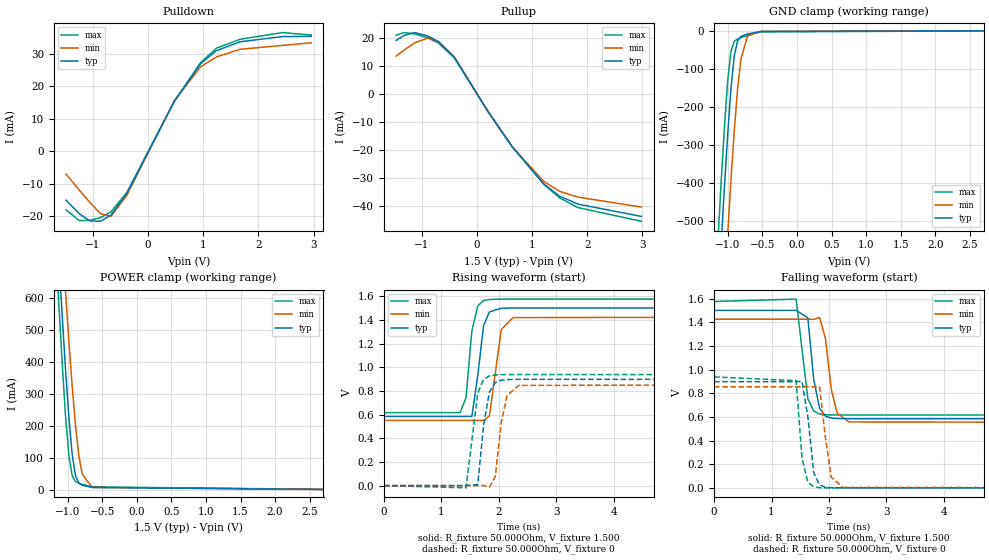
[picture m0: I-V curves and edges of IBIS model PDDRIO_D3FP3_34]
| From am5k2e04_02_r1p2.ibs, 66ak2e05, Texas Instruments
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|2.66MA OUTPUT CURRENT SETTING WITH 200 OHM INT. TERM.
|   Model PDDRIO_D3FP3_34
[Model] PDDRIO_D3FP3_34
Model_type   I/O
Polarity   Non-Inverting
Enable   Active-High
C_comp   3.236pF   3.174pF   3.318pF
C_comp_pullup   516.723fF   493.565fF   544.031fF
C_comp_pulldown 2.715pF   2.675pF   2.769pF
Vinh = 925.000mV
Vinl = 575.000mV
Vmeas = 750.000mV
Vref = 750.000mV
Rref = 50Ohms
Cref = 0pF
[Model Spec]
Vinh   925.000mV   888.000mV   963.000mV
Vinl   575.000mV   538.000mV   613.000mV
Vmeas   750.000mV   713.000mV   788.000mV
Vref   750.000mV   713.000mV   788.000mV
[Temperature Range]   25.000   125.000   -40.000
[Voltage Range]   1.500V   1.425V   1.575V
[GND Clamp Reference]   0.00V   0.00V   0.00V
|[C Comp Corner]
| variable   typ   min   max
|C_comp   3.236pF   3.318pF   3.174pF
|C_comp_pullup   516.723fF   544.031fF   493.565fF
|C_comp_pulldown   2.715pF   2.769pF   2.675pF
[Pulldown Reference]   0.00V   0.00V   0.00V
[POWER Clamp Reference]   1.500V   1.425V   1.575V
[Pullup Reference]   1.500V   1.425V   1.575V
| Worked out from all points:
|   slope of the pulldown table from 0 to 0.225 V, typ, clamps not added: 29.7 ohm
|   slope of the pullup table from 0 to 0.225 V, typ, clamps not added: 32 ohm
|   GND clamp passes 1 mA (typ) near -0.49 V on its own axis
|   POWER clamp passes 1 mA (typ) near -0.46 V on its own axis
|   rising waveform, R_fixture 50.000Ohm, V_fixture 1.500: 20-80 % time 141ps typ, 149ps min, 127ps max; typ from 0.584 V to 1.5 V
|   rising waveform, R_fixture 50.000Ohm, V_fixture 0: 20-80 % time 143ps typ, 149ps min, 143ps max; typ from 0 V to 0.898 V
|   falling waveform, R_fixture 50.000Ohm, V_fixture 1.500: 20-80 % time 141ps typ, 153ps min, 143ps max; typ from 1.5 V to 0.584 V
|   falling waveform, R_fixture 50.000Ohm, V_fixture 0: 20-80 % time 131ps typ, 139ps min, 110ps max; typ from 0.898 V to 0 V
[GND Clamp]
-1.48V    -1.918A    -2.181A    -1.764A
-1.145V   -723.4mA   -1.002A    -556.7mA
-1.098V   -563.3mA   -840.4mA   -399.2mA
-1.05V    -410.5mA   -683.3mA   -253.2mA
-1.002V   -269.5mA   -532mA     -130mA
-954.6mV  -149.1mA   -389.4mA   -52.57mA
-906.8mV  -64.77mA   -260.1mA   -27.53mA
-859.1mV  -26.06mA   -151.5mA   -21.41mA
-811.4mV  -14.61mA   -73.73mA   -17.98mA
-715.9mV  -8.245mA   -13.8mA    -12.04mA
-525mV    -1.646mA   -1.444mA   -2.745mA
2.959V    5.131nA    157.9nA    5.129nA
[Power Clamp]
-1.459V   2.052A     2.172A     2.008A
-1.173V   897.3mA    1.113A     766.5mA
-1.125V   714.9mA    943mA      572.9mA
-1.077V   539.1mA    776.9mA    390mA
-1.03V    373.7mA    616.2mA    227.4mA
-981.8mV  225.9mA    463.5mA    105.8mA
-934.1mV  109.7mA    322.9mA    43.29mA
-886.4mV  43.23mA    201.1mA    25.08mA
-838.6mV  20.27mA    107.7mA    20.03mA
-790.9mV  13.81mA    49.43mA    16.8mA
-647.7mV  6.613mA    6.926mA    8.545mA
2.98V     -9.151nA   -320.3nA   -14.09nA
[Pulldown]
-1.48V    -15mA      -7mA       -18mA
-1.241V   -19.2mA    -11.9mA    -21.3mA
-1.05V    -21.4mA    -15.7mA    -21.2mA
-859.1mV  -21.51mA   -19.1mA    -20.39mA
-668.2mV  -19.6mA    -20.06mA   -18.62mA
-381.8mV  -12.99mA   -13.57mA   -12.7mA
477.3mV   15.34mA    15.48mA    15.28mA
954.6mV   26.95mA    26.01mA    27.3mA
1.241V    30.97mA    29.06mA    31.74mA
1.67V     33.71mA    31.4mA     34.48mA
2.434V    35.3mA     32.6mA     36.55mA
2.959V    35.4mA     33.4mA     35.8mA
[Pullup]
-1.459V   19mA       13.36mA    20.87mA
-1.316V   20.8mA     15.54mA    21.8mA
-1.125V   21.8mA     18.14mA    21.31mA
-886.4mV  20.58mA    19.86mA    19.93mA
-695.5mV  18.6mA     18.6mA     18.08mA
-409.1mV  13.07mA    13.17mA    12.79mA
211.4mV   -6.617mA   -6.664mA   -6.54mA
640.9mV   -18.99mA   -18.93mA   -18.85mA
1.214V    -32.21mA   -31.33mA   -32.34mA
1.5V      -36.58mA   -34.84mA   -37.18mA
1.834V    -39.41mA   -36.92mA   -40.66mA
2.98V     -43.8mA    -40.46mA   -45.54mA
[Ramp]
R_load=50.000Ohm
dV/dt_r   544.140mV/124.000ps  518.489mV/133.000ps  569.040mV/116.000ps
dV/dt_f   544.140mV/112.500ps  518.489mV/122.500ps  569.040mV/107.000ps
[Rising waveform]
R_fixture=50.000Ohm
V_fixture=1.500
V_fixture_min=1.425
V_fixture_max=1.575
0s        583.8mV    550.7mV    615.9mV
1.327ns   583.8mV    550.7mV    616mV
1.429ns   583.8mV    550.7mV    742.7mV
1.531ns   583.7mV    550.7mV    1.307V
1.633ns   926.8mV    550.8mV    1.517V
1.735ns   1.352V     549.4mV    1.563V
1.837ns   1.467V     587.9mV    1.572V
2.042ns   1.498V     1.317V     1.575V
2.246ns   1.5V       1.419V     1.575V
10ns      1.5V       1.425V     1.575V
[Rising waveform]
R_fixture=50.000Ohm
V_fixture=0
0s        0V         1.817uV    0V
1.429ns   31.28uV    -4.413uV   -19.23mV
1.633ns   9.079mV    13.97uV    780mV
1.735ns   508.2mV    595.4uV    897.6mV
1.837ns   791.1mV    -12.61mV   926.8mV
1.939ns   869.8mV    76.84mV    934.7mV
2.042ns   889.7mV    530.4mV    936.9mV
2.144ns   895.2mV    761.1mV    937.5mV
2.348ns   897.4mV    846.2mV    937.7mV
10ns      897.6mV    854mV      937.7mV
[Falling waveform]
R_fixture=50.000Ohm
V_fixture=1.500
V_fixture_min=1.425
V_fixture_max=1.575
0s        1.5V       1.425V     1.575V
1.429ns   1.5V       1.425V     1.595V
1.633ns   1.436V     1.425V     752.2mV
1.735ns   917.1mV    1.424V     649.2mV
1.837ns   671.9mV    1.44V      624.7mV
1.939ns   606.3mV    1.265V     618.2mV
2.042ns   590mV      830.6mV    616.5mV
2.144ns   585.6mV    631.8mV    616.1mV
2.348ns   583.9mV    557.3mV    615.9mV
10ns      583.8mV    550.7mV    615.9mV
[Falling waveform]
R_fixture=50.000Ohm
V_fixture=0
0s        897.6mV    854mV      937.7mV
1.429ns   897.6mV    854mV      906.4mV
1.531ns   899.6mV    854mV      251.3mV
1.633ns   601.6mV    854mV      48mV
1.735ns   128.5mV    853.8mV    9.098mV
1.837ns   25.25mV    854.6mV    1.631mV
1.939ns   4.886mV    424.7mV    370.7uV
2.042ns   874.4uV    88.61mV    -26.56uV
2.246ns   25.9uV     3.703mV    0V
10ns      0V         1.816uV    0V
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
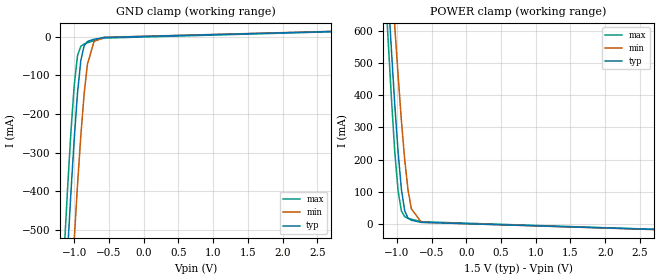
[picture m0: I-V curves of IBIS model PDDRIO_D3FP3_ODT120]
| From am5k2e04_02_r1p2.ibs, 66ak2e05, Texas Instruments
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|   Model PDDRIO_D3FP3_ODT120
[Model] PDDRIO_D3FP3_ODT120
Model_type   Input
Polarity   Non-Inverting
Enable   Active-High
C_comp   3.260pF   3.200pF   3.350pF
C_comp_pullup   547.386fF   525.260fF   584.423fF
C_comp_pulldown 2.708pF   2.670pF   2.760pF
Vinh = 925.000mV
Vinl = 575.000mV
[Temperature Range]   25.000   125.000   -40.000
[Voltage Range]   1.500V   1.425V   1.575V
[GND Clamp Reference]   0.00V   0.00V   0.00V
|[C Comp Corner]
| variable   typ   min   max
|C_comp 3.260pF   3.350pF   3.200pF
|C_comp_pullup 547.386fF   584.423fF   525.260fF
|C_comp_pulldown 2.708pF   2.760pF   2.670pF
[POWER Clamp Reference]   1.500V   1.425V   1.575V
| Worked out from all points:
|   GND clamp passes 1 mA (typ) near -0.53 V on its own axis
|   POWER clamp passes 1 mA (typ) near -0.47 V on its own axis
[GND Clamp]
-1.48V    -1.91A     -2.171A    -1.756A
-1.145V   -718.6mA   -995.7mA   -552.2mA
-1.098V   -559mA     -835mA     -395.1mA
-1.05V    -406.6mA   -678.3mA   -249.4mA
-1.002V   -266mA     -527.6mA   -126.5mA
-954.6mV  -146mA     -385.5mA   -49.45mA
-906.8mV  -62.03mA   -256.7mA   -24.72mA
-859.1mV  -23.65mA   -148.6mA   -18.89mA
-811.4mV  -12.49mA   -71.22mA   -15.74mA
-715.9mV  -6.656mA   -12.08mA   -10.34mA
-572.7mV  -1.961mA   -1.652mA   -3.583mA
2.959V    14.61mA    15.11mA    14.06mA
[Power Clamp]
-1.459V   2.046A     2.165A     2.003A
-1.173V   893.9mA    1.109A     763.1mA
-1.125V   711.7mA    939.1mA    569.8mA
-1.077V   536.2mA    773.5mA    387.1mA
-1.03V    371.1mA    613.2mA    224.9mA
-981.8mV  223.5mA    460.9mA    103.5mA
-934.1mV  107.7mA    320.6mA    41.3mA
-886.4mV  41.46mA    199.1mA    23.34mA
-838.6mV  18.76mA    106mA      18.52mA
-790.9mV  12.5mA     48.03mA    15.49mA
-647.7mV  5.868mA    6.184mA    7.808mA
2.98V     -17.73mA   -18.38mA   -17.59mA
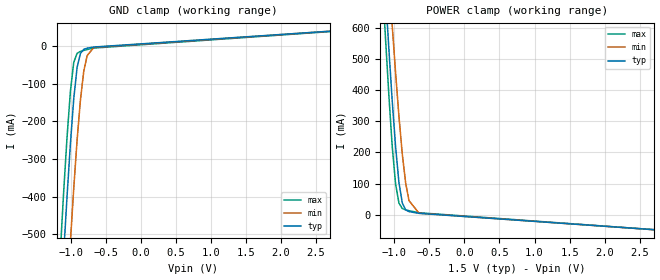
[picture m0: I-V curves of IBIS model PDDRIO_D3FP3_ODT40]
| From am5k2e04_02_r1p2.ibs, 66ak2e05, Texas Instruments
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|   Model PDDRIO_D3FP3_ODT40
[Model] PDDRIO_D3FP3_ODT40
Model_type   Input
Polarity   Non-Inverting
Enable   Active-High
C_comp   3.309pF   3.232pF   3.410pF
C_comp_pullup   607.833fF   563.222fF   663.200fF
C_comp_pulldown 2.696pF   2.664pF   2.742pF
Vinh = 925.000mV
Vinl = 575.000mV
[Temperature Range]   25.000   125.000   -40.000
[Voltage Range]   1.500V   1.425V   1.575V
[GND Clamp Reference]   0.00V   0.00V   0.00V
|[C Comp Corner]
| variable   typ   min   max
|C_comp 3.309pF   3.410pF   3.232pF
|C_comp_pullup 607.833fF   663.200fF   563.222fF
|C_comp_pulldown 2.696pF   2.742pF   2.664pF
[POWER Clamp Reference]   1.500V   1.425V   1.575V
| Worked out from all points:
|   GND clamp passes 1 mA (typ) near -0.62 V on its own axis
|   POWER clamp passes 1 mA (typ) near -0.51 V on its own axis
[GND Clamp]
-1.48V    -1.895A    -2.153A    -1.741A
-1.145V   -709.5mA   -984.5mA   -543.3mA
-1.098V   -550.7mA   -824.6mA   -386.7mA
-1.05V    -399.2mA   -669mA     -241.7mA
-1.002V   -259.3mA   -519.2mA   -119.6mA
-954.6mV  -140.1mA   -378mA     -43.12mA
-906.8mV  -56.72mA   -250.1mA   -19.02mA
-859.1mV  -18.96mA   -142.9mA   -13.8mA
-811.4mV  -8.364mA   -66.45mA   -11.23mA
-763.6mV  -5.242mA   -25.24mA   -9.016mA
-668.2mV  -2.238mA   -3.25mA    -4.954mA
2.959V    43.1mA     43.05mA    42.16mA
[Power Clamp]
-1.459V   2.035A     2.153A     1.992A
-1.173V   887.1mA    1.101A     756.5mA
-1.125V   705.6mA    932mA      563.6mA
-1.077V   530.6mA    767.1mA    381.5mA
-1.03V    366mA      607.5mA    219.8mA
-981.8mV  219mA      455.8mA    99.02mA
-934.1mV  103.7mA    316.2mA    37.4mA
-886.4mV  38.01mA    195.4mA    19.95mA
-838.6mV  15.8mA     102.8mA    15.55mA
-790.9mV  9.964mA    45.44mA    12.94mA
-647.7mV  4.428mA    4.813mA    6.354mA
2.98V     -52.32mA   -52.48mA   -52.49mA
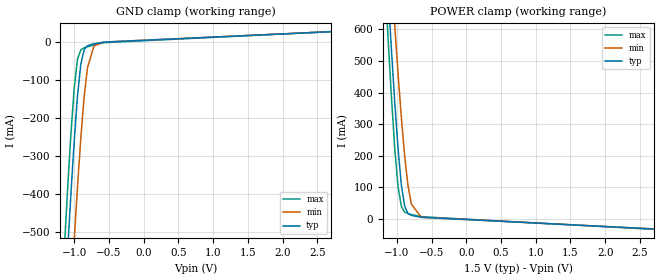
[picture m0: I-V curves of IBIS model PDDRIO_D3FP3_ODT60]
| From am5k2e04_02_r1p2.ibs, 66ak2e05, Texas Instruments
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|   Model PDDRIO_D3FP3_ODT60
[Model] PDDRIO_D3FP3_ODT60
Model_type   Input
Polarity   Non-Inverting
Enable   Active-High
C_comp   3.286pF   3.226pF   3.386pF
C_comp_pullup   579.570fF   555.779fF   632.377fF
C_comp_pulldown 2.701pF   2.664pF   2.749pF
Vinh = 925.000mV
Vinl = 575.000mV
[Temperature Range]   25.000   125.000   -40.000
[Voltage Range]   1.500V   1.425V   1.575V
[GND Clamp Reference]   0.00V   0.00V   0.00V
|[C Comp Corner]
|| variable   typ   min   max
|C_comp 3.286pF   3.386pF   3.226pF
|C_comp_pullup 579.570fF   632.377fF   555.779fF
|C_comp_pulldown 2.701pF   2.749pF   2.664pF
[POWER Clamp Reference]   1.500V   1.425V   1.575V
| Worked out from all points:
|   GND clamp passes 1 mA (typ) near -0.57 V on its own axis
|   POWER clamp passes 1 mA (typ) near -0.49 V on its own axis
[GND Clamp]
-1.48V    -1.903A    -2.162A    -1.748A
-1.145V   -714.3mA   -990.3mA   -547.5mA
-1.098V   -555mA     -830mA     -390.6mA
-1.05V    -403mA     -673.8mA   -245.3mA
-1.002V   -262.8mA   -523.6mA   -122.8mA
-954.6mV  -143.1mA   -382mA     -46.1mA
-906.8mV  -59.45mA   -253.5mA   -21.71mA
-859.1mV  -21.36mA   -145.9mA   -16.2mA
-811.4mV  -10.48mA   -68.97mA   -13.36mA
-715.9mV  -5.153mA   -10.58mA   -8.539mA
-572.7mV  -1.072mA   -892.8uA   -2.551mA
2.959V    28.5mA     28.54mA    29.03mA
[Power Clamp]
-1.459V   2.041A     2.159A     1.997A
-1.173V   890.5mA    1.105A     759.5mA
-1.125V   708.7mA    935.7mA    566.5mA
-1.077V   533.5mA    770.4mA    384.2mA
-1.03V    368.6mA    610.4mA    222.1mA
-981.8mV  221.3mA    458.4mA    101.1mA
-934.1mV  105.7mA    318.4mA    39.23mA
-886.4mV  39.75mA    197.3mA    21.55mA
-838.6mV  17.3mA     104.4mA    16.95mA
-790.9mV  11.26mA    46.79mA    14.14mA
-647.7mV  5.169mA    5.52mA     7.041mA
2.98V     -34.6mA    -34.72mA   -36.16mA
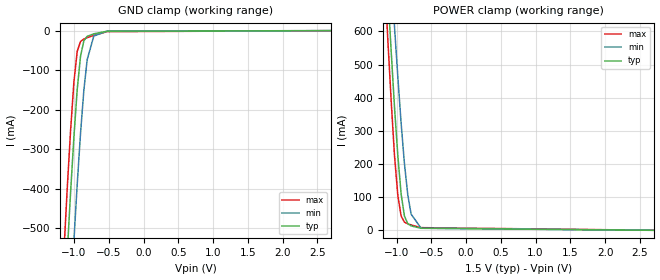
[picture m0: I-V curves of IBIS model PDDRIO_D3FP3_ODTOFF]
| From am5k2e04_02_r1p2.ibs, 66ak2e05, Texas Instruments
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|   Model PDDRIO_D3FP3_ODTOFF
[Model] PDDRIO_D3FP3_ODTOFF
Model_type   Input
Polarity   Non-Inverting
Enable   Active-High
C_comp   3.236pF   3.174pF   3.318pF
C_comp_pullup   530.516fF   508.082fF   557.434fF
C_comp_pulldown 2.701pF   2.661pF   2.755pF
Vinh = 925.000mV
Vinl = 575.000mV
[Temperature Range]   25.000   125.000   -40.000
[Voltage Range]   1.500V   1.425V   1.575V
[GND Clamp Reference]   0.00V   0.00V   0.00V
|[C Comp Corner]
|| variable   typ   min   max
|C_comp 3.236pF   3.318pF   3.174pF
|C_comp_pullup 530.516fF   557.434fF   508.082fF
|C_comp_pulldown 2.701pF   2.755pF   2.661pF
[POWER Clamp Reference]   1.500V   1.425V   1.575V
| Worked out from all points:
|   GND clamp passes 1 mA (typ) near -0.49 V on its own axis
|   POWER clamp passes 1 mA (typ) near -0.46 V on its own axis
[GND Clamp]
-1.48V    -1.918A    -2.181A    -1.764A
-1.145V   -723.4mA   -1.002A    -556.7mA
-1.098V   -563.3mA   -840.4mA   -399.2mA
-1.05V    -410.5mA   -683.3mA   -253.2mA
-1.002V   -269.5mA   -532mA     -130mA
-954.6mV  -149.1mA   -389.4mA   -52.57mA
-906.8mV  -64.77mA   -260.1mA   -27.53mA
-859.1mV  -26.06mA   -151.5mA   -21.41mA
-811.4mV  -14.61mA   -73.73mA   -17.98mA
-715.9mV  -8.245mA   -13.8mA    -12.04mA
-525mV    -1.646mA   -1.444mA   -2.745mA
2.959V    5.131nA    157.9nA    7.042nA
[Power Clamp]
-1.459V   2.052A     2.172A     2.008A
-1.173V   897.3mA    1.113A     766.5mA
-1.125V   714.9mA    943mA      572.9mA
-1.077V   539.1mA    776.9mA    390mA
-1.03V    373.7mA    616.2mA    227.4mA
-981.8mV  225.9mA    463.5mA    105.8mA
-934.1mV  109.7mA    322.9mA    43.29mA
-886.4mV  43.23mA    201.1mA    25.08mA
-838.6mV  20.27mA    107.7mA    20.03mA
-790.9mV  13.81mA    49.43mA    16.8mA
-647.7mV  6.613mA    6.926mA    8.545mA
2.98V     -9.151nA   -320.3nA   -14.09nA
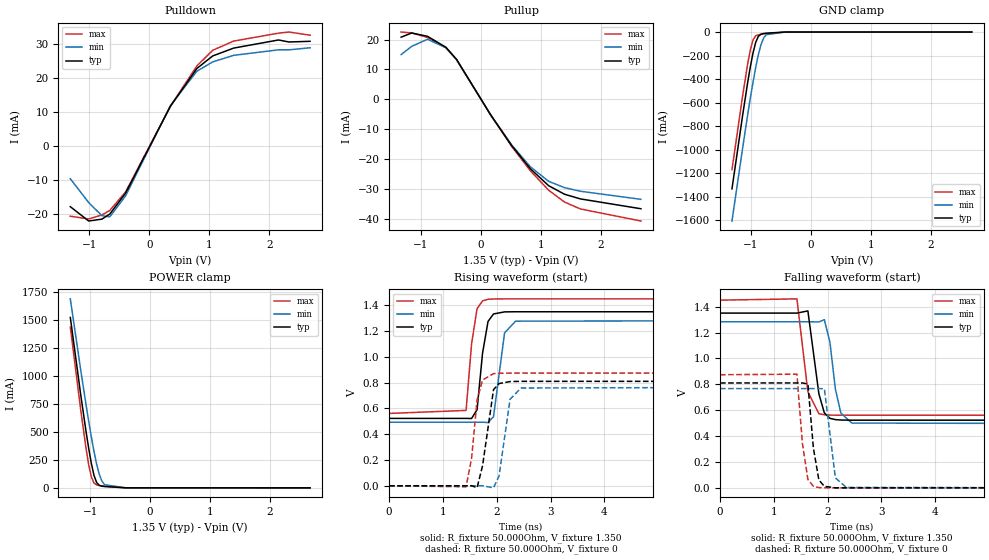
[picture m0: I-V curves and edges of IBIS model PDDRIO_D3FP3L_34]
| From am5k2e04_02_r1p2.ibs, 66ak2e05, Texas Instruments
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|   Model PDDRIO_D3FP3L_34
[Model] PDDRIO_D3FP3L_34
Model_type   I/O
Polarity   Non-Inverting
Enable   Active-High
C_comp   3.244pF   3.179pF   3.327pF
C_comp_pullup   525.014fF   499.307fF   553.259fF
C_comp_pulldown 2.714pF   2.675pF   2.768pF
Vinh = 810.000mV
Vinl = 540.000mV
Vmeas = 675.000mV
Vref = 675.000mV
Rref = 50Ohms
Cref = 0pF
[Model Spec]
Vinh   810.000mV   777.000mV   860.000mV
Vinl   540.000mV   507.000mV   590.000mV
Vmeas   675.000mV   642.000mV   725.000mV
Vref   675.000mV   642.000mV   725.000mV
[Temperature Range]   25.000   125.000   -40.000
[Voltage Range]   1.350V   1.283V   1.450V
[GND Clamp Reference]   0.00V   0.00V   0.00V
|[C Comp Corner]
| variable   typ   min   max
|C_comp 3.244pF   3.327pF   3.179pF
|C_comp_pullup 525.014fF   553.259fF   499.307fF
|C_comp_pulldown 2.714pF   2.768pF   2.675pF
[Pulldown Reference]   0.00V   0.00V   0.00V
[POWER Clamp Reference]   1.350V   1.283V   1.450V
[Pullup Reference]   1.350V   1.283V   1.450V
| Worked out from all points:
|   slope of the pulldown table from 0 to 0.203 V, typ, clamps not added: 29.1 ohm
|   slope of the pullup table from 0 to 0.203 V, typ, clamps not added: 31.5 ohm
|   GND clamp passes 1 mA (typ) near -0.49 V on its own axis
|   POWER clamp passes 1 mA (typ) near -0.46 V on its own axis
|   rising waveform, R_fixture 50.000Ohm, V_fixture 1.350: 20-80 % time 144ps typ, 151ps min, 136ps max; typ from 0.523 V to 1.35 V
|   rising waveform, R_fixture 50.000Ohm, V_fixture 0: 20-80 % time 144ps typ, 156ps min, 141ps max; typ from 0 V to 0.81 V
|   falling waveform, R_fixture 50.000Ohm, V_fixture 1.350: 20-80 % time 157ps typ, 163ps min, 142ps max; typ from 1.35 V to 0.523 V
|   falling waveform, R_fixture 50.000Ohm, V_fixture 0: 20-80 % time 130ps typ, 139ps min, 130ps max; typ from 0.81 V to 0 V
[GND Clamp]
-1.318V   -1.332A    -1.605A    -1.169A
-1.142V   -713.1mA   -991.3mA   -546.4mA
-1.055V   -424.6mA   -698mA     -266.3mA
-1.011V   -292.9mA   -557.9mA   -149mA
-966.7mV  -177mA     -424.6mA   -66.54mA
-922.7mV  -87.81mA   -301.3mA   -32.09mA
-878.8mV  -37.14mA   -193.2mA   -23.25mA
-834.9mV  -18.49mA   -107.6mA   -19.58mA
-790.9mV  -12.57mA   -51.47mA   -16.65mA
-747mV    -9.756mA   -23.13mA   -13.9mA
-439.4mV  -371uA     -394.7uA   -656.8uA
2.68V     4.17nA     252.6nA    2.491nA
[Power Clamp]
-1.33V    1.525A     1.691A     1.439A
-1.155V   827.2mA    1.048A     691.5mA
-1.067V   501.3mA    740.6mA    350.5mA
-1.023V   351.3mA    593.8mA    204.8mA
-978.8mV  217.4mA    454mA      97mA
-934.9mV  111.2mA    324.7mA    43.08mA
-890.9mV  47.28mA    211.3mA    25.9mA
-847mV    22.44mA    121mA      20.68mA
-803mV    14.88mA    60.26mA    17.58mA
-759.1mV  11.71mA    27.92mA    14.82mA
-407.6mV  326.5uA    576uA      395.5uA
2.668V    -7.545nA   -288.5nA   -3.819nA
[Pulldown]
-1.318V   -17.8mA    -9.6mA     -20.6mA
-1.011V   -22mA      -16.6mA    -21.4mA
-790.9mV  -21.45mA   -20.44mA   -20.23mA
-659.1mV  -19.95mA   -20.77mA   -18.89mA
-395.5mV  -13.8mA    -14.61mA   -13.44mA
351.5mV   11.67mA    11.86mA    11.67mA
790.9mV   22.71mA    21.91mA    23.45mA
1.055V    26.4mA     24.66mA    28.06mA
1.406V    28.71mA    26.59mA    30.77mA
2.153V    31.09mA    28.2mA     33.09mA
2.329V    30.5mA     28.2mA     33.42mA
2.68V     30.7mA     28.8mA     32.5mA
[Pullup]
-1.33V    20.8mA     14.97mA    22.52mA
-1.155V   22.2mA     17.72mA    22.23mA
-890.9mV  21.09mA    20.1mA     20.71mA
-583.3mV  17.42mA    17.28mA    17.21mA
-407.6mV  13.39mA    13.38mA    13.29mA
163.6mV   -5.229mA   -5.207mA   -5.266mA
515.1mV   -15.54mA   -15.31mA   -15.79mA
822.7mV   -23.18mA   -22.52mA   -23.85mA
1.13V     -28.9mA    -27.44mA   -30.41mA
1.394V    -31.74mA   -29.54mA   -34.35mA
1.658V    -33.3mA    -30.74mA   -36.66mA
2.668V    -36.6mA    -33.45mA   -40.7mA
[Ramp]
R_load=50.000Ohm
dV/dt_r   491.250mV/127.500ps  467.070mV/138.000ps  528.840mV/117.000ps
dV/dt_f   491.250mV/117.500ps  467.070mV/128.500ps  528.840mV/109.000ps
[Rising waveform]
R_fixture=50.000Ohm
V_fixture=1.350
V_fixture_min=1.283
V_fixture_max=1.450
0s        522.7mV    493.1mV    561.2mV
1.429ns   522.7mV    493.1mV    584.7mV
1.531ns   522mV      493.2mV    1.1V
1.633ns   589.6mV    493.2mV    1.374V
1.735ns   1.029V     493.2mV    1.434V
1.837ns   1.275V     490.4mV    1.447V
1.939ns   1.333V     535.8mV    1.449V
2.144ns   1.349V     1.186V     1.45V
2.348ns   1.35V      1.277V     1.45V
10ns      1.35V      1.283V     1.45V
[Rising waveform]
R_fixture=50.000Ohm
V_fixture=0
0s        0V         1.612uV    0V
1.429ns   -3.209uV   -2.435uV   -7.957mV
1.531ns   268.9uV    4.198uV    210.7mV
1.633ns   -15.18mV   -5.69uV    666mV
1.735ns   154.9mV    12.74uV    820.5mV
1.939ns   746mV      -16.11mV   870mV
2.042ns   792.8mV    77.12mV    873mV
2.246ns   808.6mV    670.8mV    874mV
2.45ns    810.1mV    758.4mV    874mV
10ns      810.2mV    767mV      874mV
[Falling waveform]
R_fixture=50.000Ohm
V_fixture=1.350
V_fixture_min=1.283
V_fixture_max=1.450
0s        1.35V      1.283V     1.45V
1.429ns   1.35V      1.283V     1.46V
1.633ns   1.367V     1.283V     741.7mV
1.837ns   726.7mV    1.282V     572.7mV
1.939ns   578.8mV    1.299V     564.3mV
2.042ns   537.2mV    1.126V     562mV
2.144ns   527.1mV    762.3mV    561.4mV
2.246ns   524mV      577.3mV    561.3mV
2.45ns    522.8mV    500.6mV    561.2mV
10ns      522.7mV    493.1mV    561.2mV
[Falling waveform]
R_fixture=50.000Ohm
V_fixture=0
0s        810.2mV    767mV      874mV
1.429ns   810.3mV    767mV      878mV
1.531ns   810.1mV    767mV      343.6mV
1.633ns   802.8mV    767mV      65.29mV
1.735ns   307.7mV    766.9mV    12.1mV
1.837ns   60.73mV    767.2mV    2.23mV
1.939ns   11.86mV    765mV      389.5uV
2.144ns   405.8uV    76.53mV    9.251uV
2.348ns   9.743uV    3.208mV    0V
10ns      0V         1.616uV    0V
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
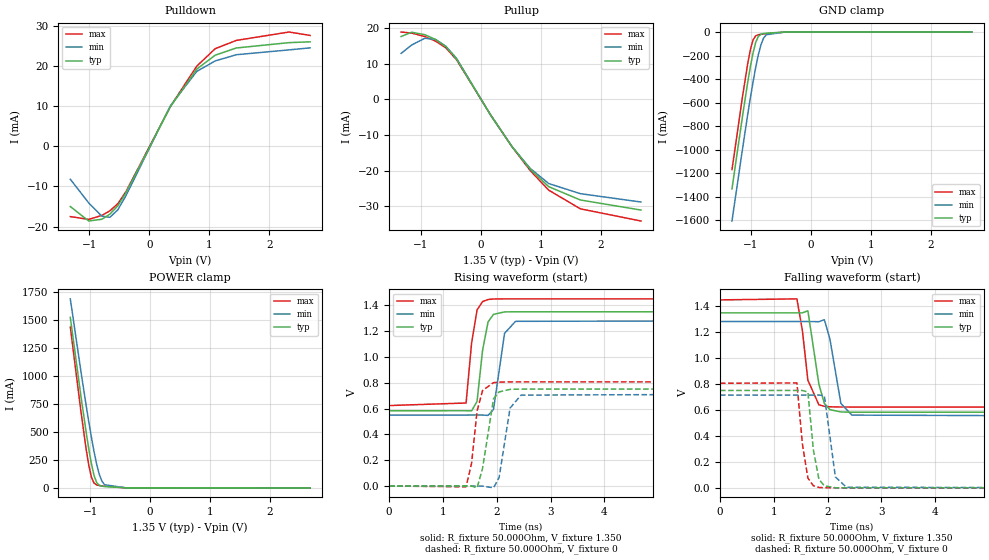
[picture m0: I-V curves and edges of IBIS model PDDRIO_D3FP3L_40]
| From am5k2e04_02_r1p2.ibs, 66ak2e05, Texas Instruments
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|   Model PDDRIO_D3FP3L_40
[Model] PDDRIO_D3FP3L_40
Model_type   I/O
Polarity   Non-Inverting
Enable   Active-High
C_comp   3.244pF   3.179pF   3.327pF
C_comp_pullup   525.014fF   499.307fF   553.259fF
C_comp_pulldown 2.714pF   2.675pF   2.768pF
Vinh = 810.000mV
Vinl = 540.000mV
Vmeas = 675.000mV
Vref = 675.000mV
Rref = 50Ohms
Cref = 0pF
[Model Spec]
Vinh   810.000mV   777.000mV   860.000mV
Vinl   540.000mV   507.000mV   590.000mV
Vmeas   675.000mV   642.000mV   725.000mV
Vref   675.000mV   642.000mV   725.000mV
[Temperature Range]   25.000   125.000   -40.000
[Voltage Range]   1.350V   1.283V   1.450V
[GND Clamp Reference]   0.00V   0.00V   0.00V
|[C Comp Corner]
| variable   typ   min   max
|C_comp 3.244pF   3.327pF   3.179pF
|C_comp_pullup 525.014fF   553.259fF   499.307fF
|C_comp_pulldown 2.714pF   2.768pF   2.675pF
[Pulldown Reference]   0.00V   0.00V   0.00V
[POWER Clamp Reference]   1.350V   1.283V   1.450V
[Pullup Reference]   1.350V   1.283V   1.450V
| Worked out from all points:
|   slope of the pulldown table from 0 to 0.203 V, typ, clamps not added: 34.4 ohm
|   slope of the pullup table from 0 to 0.203 V, typ, clamps not added: 37.2 ohm
|   GND clamp passes 1 mA (typ) near -0.49 V on its own axis
|   POWER clamp passes 1 mA (typ) near -0.46 V on its own axis
|   rising waveform, R_fixture 50.000Ohm, V_fixture 1.350: 20-80 % time 149ps typ, 155ps min, 141ps max; typ from 0.583 V to 1.35 V
|   rising waveform, R_fixture 50.000Ohm, V_fixture 0: 20-80 % time 155ps typ, 165ps min, 152ps max; typ from 0 V to 0.751 V
|   falling waveform, R_fixture 50.000Ohm, V_fixture 1.350: 20-80 % time 170ps typ, 174ps min, 161ps max; typ from 1.35 V to 0.583 V
|   falling waveform, R_fixture 50.000Ohm, V_fixture 0: 20-80 % time 135ps typ, 143ps min, 135ps max; typ from 0.751 V to 0 V
[GND Clamp]
-1.318V   -1.332A    -1.605A    -1.169A
-1.142V   -713.1mA   -991.3mA   -546.4mA
-1.055V   -424.6mA   -698mA     -266.3mA
-1.011V   -292.9mA   -557.9mA   -149mA
-966.7mV  -177mA     -424.6mA   -66.54mA
-922.7mV  -87.81mA   -301.3mA   -32.09mA
-878.8mV  -37.14mA   -193.2mA   -23.25mA
-834.9mV  -18.49mA   -107.6mA   -19.58mA
-790.9mV  -12.57mA   -51.47mA   -16.65mA
-747mV    -9.756mA   -23.13mA   -13.9mA
-439.4mV  -371uA     -394.7uA   -656.8uA
2.68V     4.17nA     252.6nA    785.5pA
[Power Clamp]
-1.33V    1.525A     1.691A     1.439A
-1.155V   827.2mA    1.048A     691.5mA
-1.067V   501.3mA    740.6mA    350.5mA
-1.023V   351.3mA    593.8mA    204.8mA
-978.8mV  217.4mA    454mA      97mA
-934.9mV  111.2mA    324.7mA    43.08mA
-890.9mV  47.28mA    211.3mA    25.9mA
-847mV    22.44mA    121mA      20.68mA
-803mV    14.88mA    60.26mA    17.58mA
-759.1mV  11.71mA    27.92mA    14.82mA
-407.6mV  326.4uA    576uA      395.5uA
2.668V    -7.545nA   -288.5nA   181.4pA
[Pulldown]
-1.318V   -15mA      -8.2mA     -17.5mA
-1.011V   -18.6mA    -14.1mA    -18.2mA
-790.9mV  -18.16mA   -17.4mA    -17.2mA
-659.1mV  -16.89mA   -17.68mA   -16.07mA
-527.3mV  -14.84mA   -15.84mA   -14.31mA
-395.5mV  -11.68mA   -12.44mA   -11.43mA
351.5mV   9.877mA    10.1mA     9.93mA
790.9mV   19.22mA    18.65mA    19.95mA
1.098V    22.68mA    21.25mA    24.3mA
1.45V     24.47mA    22.79mA    26.36mA
2.329V    25.8mA     24mA       28.44mA
2.68V     26mA       24.5mA     27.6mA
[Pullup]
-1.33V    17.6mA     12.87mA    18.85mA
-1.155V   18.8mA     15.21mA    18.55mA
-934.9mV  18.1mA     17.11mA    17.59mA
-759.1mV  16.79mA    16.79mA    16.33mA
-583.3mV  14.74mA    14.85mA    14.4mA
-407.6mV  11.33mA    11.5mA     11.12mA
163.6mV   -4.424mA   -4.475mA   -4.405mA
515.1mV   -13.15mA   -13.16mA   -13.21mA
822.7mV   -19.61mA   -19.35mA   -19.95mA
1.13V     -24.45mA   -23.58mA   -25.43mA
1.658V    -28.18mA   -26.41mA   -30.65mA
2.668V    -31mA      -28.75mA   -34.07mA
[Ramp]
R_load=50.000Ohm
dV/dt_r   455.430mV/137.500ps  434.609mV/148.500ps  490.050mV/127.000ps
dV/dt_f   455.430mV/128.000ps  434.609mV/139.500ps  490.050mV/119.500ps
[Rising waveform]
R_fixture=50.000Ohm
V_fixture=1.350
V_fixture_min=1.283
V_fixture_max=1.450
0s        583.3mV    550.1mV    623.5mV
1.429ns   583.4mV    550.1mV    643.2mV
1.531ns   582.5mV    550.2mV    1.106V
1.633ns   655.7mV    550.2mV    1.364V
1.735ns   1.05V      550.2mV    1.429V
1.837ns   1.271V     547.1mV    1.445V
1.939ns   1.33V      593.7mV    1.449V
2.144ns   1.349V     1.183V     1.45V
2.348ns   1.35V      1.276V     1.45V
10ns      1.35V      1.283V     1.45V
[Rising waveform]
R_fixture=50.000Ohm
V_fixture=0
0s        0V         1.784uV    0V
1.429ns   -2.136uV   -2.275uV   -6.185mV
1.531ns   261uV      4.249uV    176.1mV
1.633ns   -14.09mV   -4.032uV   579.8mV
1.735ns   136.6mV    8.763uV    740.4mV
1.939ns   675.6mV    -14.02mV   800.9mV
2.042ns   729.1mV    65.43mV    804.9mV
2.246ns   748.9mV    603.8mV    806.8mV
2.45ns    751mV      704.3mV    807mV
10ns      751.4mV    715.8mV    807mV
[Falling waveform]
R_fixture=50.000Ohm
V_fixture=1.350
V_fixture_min=1.283
V_fixture_max=1.450
0s        1.35V      1.283V     1.45V
1.429ns   1.35V      1.283V     1.458V
1.531ns   1.35V      1.283V     1.213V
1.633ns   1.366V     1.283V     830.3mV
1.837ns   800.1mV    1.282V     640.6mV
1.939ns   651.4mV    1.297V     628.9mV
2.042ns   603.3mV    1.148V     625.3mV
2.246ns   585.6mV    651.3mV    623.6mV
2.45ns    583.6mV    561.2mV    623.5mV
10ns      583.3mV    550.1mV    623.5mV
[Falling waveform]
R_fixture=50.000Ohm
V_fixture=0
0s        751.4mV    715.8mV    807mV
1.429ns   751.4mV    715.8mV    809.2mV
1.531ns   751.3mV    715.8mV    337.9mV
1.633ns   739.4mV    715.8mV    74.92mV
1.735ns   292.7mV    715.8mV    16.01mV
1.837ns   67.17mV    716.2mV    3.35mV
1.939ns   15.09mV    711.3mV    699.7uV
2.144ns   699.2uV    84.24mV    21.8uV
2.348ns   29.05uV    4.509mV    581.7nV
10ns      0V         1.783uV    0V
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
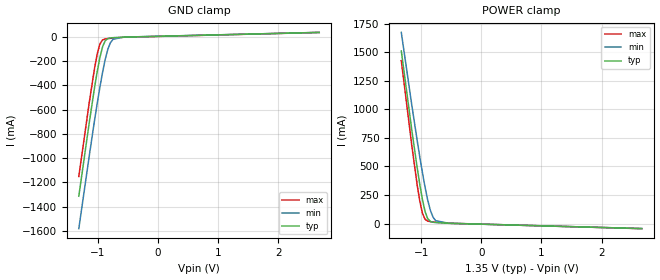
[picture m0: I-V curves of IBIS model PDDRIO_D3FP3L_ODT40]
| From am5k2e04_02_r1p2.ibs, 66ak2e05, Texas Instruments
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|   Model PDDRIO_D3FP3L_ODT40
[Model] PDDRIO_D3FP3L_ODT40
Model_type   Input
Polarity   Non-Inverting
Enable   Active-High
C_comp   3.382pF   3.290pF   3.488pF
C_comp_pullup   679.180fF   622.130fF   739.620fF
C_comp_pulldown 2.698pF   2.662pF   2.743pF
Vinh = 810.000mV
Vinl = 540.000mV
[Temperature Range]   25.000   125.000   -40.000
[Voltage Range]   1.350V   1.283V   1.450V
[GND Clamp Reference]   0.00V   0.00V   0.00V
|[C Comp Corner]
| variable   typ   min   max
|C_comp 3.382pF   3.488pF   3.290pF
|C_comp_pullup 679.180fF   739.620fF   622.130fF
|C_comp_pulldown 2.698pF   2.743pF   2.662pF
[POWER Clamp Reference]   1.350V   1.283V   1.450V
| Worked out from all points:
|   GND clamp passes 1 mA (typ) near -0.59 V on its own axis
|   POWER clamp passes 1 mA (typ) near -0.49 V on its own axis
[GND Clamp]
-1.318V   -1.315A    -1.583A    -1.152A
-1.142V   -700.3mA   -975mA     -533.5mA
-1.055V   -414.1mA   -684.4mA   -255.3mA
-1.011V   -283.4mA   -545.6mA   -138.8mA
-966.7mV  -168.5mA   -413.6mA   -57.25mA
-922.7mV  -80.27mA   -291.7mA   -23.67mA
-878.8mV  -30.43mA   -184.9mA   -15.65mA
-834.9mV  -12.56mA   -100.5mA   -12.76mA
-790.9mV  -7.364mA   -45.58mA   -10.6mA
-747mV    -5.246mA   -18.33mA   -8.59mA
-571.2mV  -624.2uA   -682.8uA   -1.81mA
2.68V     38.38mA    38.18mA    37.84mA
[Power Clamp]
-1.33V    1.512A     1.675A     1.427A
-1.155V   817.7mA    1.036A     681.9mA
-1.067V   493.2mA    731.3mA    342.3mA
-1.023V   344mA      585.5mA    197.3mA
-978.8mV  210.8mA    446.8mA    90.37mA
-934.9mV  105.5mA    318.4mA    37.31mA
-890.9mV  42.28mA    205.8mA    20.82mA
-847mV    18.12mA    116.3mA    16.21mA
-803mV    11.16mA    56.45mA    13.68mA
-759.1mV  8.54mA     24.8mA     11.48mA
-539.4mV  1.878mA    2.102mA    2.568mA
2.668V    -44.29mA   -44.5mA    -45.1mA
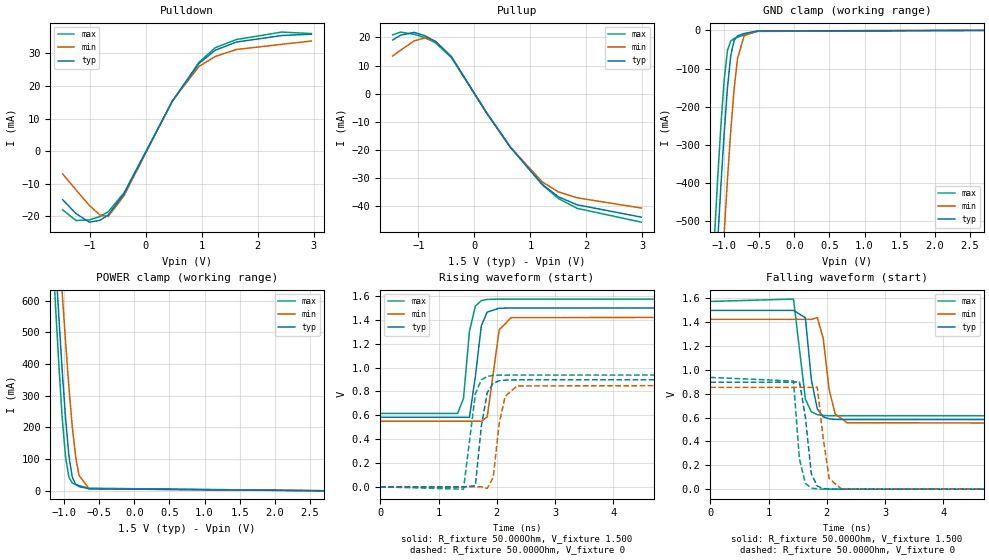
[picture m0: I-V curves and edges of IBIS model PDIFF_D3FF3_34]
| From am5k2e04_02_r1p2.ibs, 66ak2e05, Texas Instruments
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|   Model PDIFF_D3FF3_34
[Model] PDIFF_D3FF3_34
Model_type   I/O
Polarity   Non-Inverting
Enable   Active-High
C_comp   3.251pF   3.188pF   3.332pF
C_comp_pullup   516.830fF   493.667fF   544.031fF
C_comp_pulldown 2.728pF   2.688pF   2.782pF
Vinh = 925.000mV
Vinl = 575.000mV
Vmeas = 750.000mV
Vref = 750.000mV
Rref = 50Ohms
Cref = 0pF
[Model Spec]
Vinh   925.000mV   888.000mV   963.000mV
Vinl   575.000mV   538.000mV   613.000mV
Vmeas   750.000mV   713.000mV   788.000mV
Vref   750.000mV   713.000mV   788.000mV
[Temperature Range]   25.000   125.000   -40.000
[Voltage Range]   1.500V   1.425V   1.575V
[GND Clamp Reference]   0.00V   0.00V   0.00V
|[C Comp Corner]
| variable   typ   min   max
|C_comp 3.251pF   3.332pF   3.188pF
|C_comp_pullup 516.830fF   544.031fF   493.667fF
|C_comp_pulldown 2.728pF   2.782pF   2.688pF
[Pulldown Reference]   0.00V   0.00V   0.00V
[POWER Clamp Reference]   1.500V   1.425V   1.575V
[Pullup Reference]   1.500V   1.425V   1.575V
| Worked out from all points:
|   slope of the pulldown table from 0 to 0.225 V, typ, clamps not added: 29.7 ohm
|   slope of the pullup table from 0 to 0.225 V, typ, clamps not added: 32 ohm
|   GND clamp passes 1 mA (typ) near -0.49 V on its own axis
|   POWER clamp passes 1 mA (typ) near -0.46 V on its own axis
|   rising waveform, R_fixture 50.000Ohm, V_fixture 1.500: 20-80 % time 141ps typ, 149ps min, 128ps max; typ from 0.584 V to 1.5 V
|   rising waveform, R_fixture 50.000Ohm, V_fixture 0: 20-80 % time 143ps typ, 150ps min, 143ps max; typ from 0 V to 0.898 V
|   falling waveform, R_fixture 50.000Ohm, V_fixture 1.500: 20-80 % time 142ps typ, 154ps min, 143ps max; typ from 1.5 V to 0.584 V
|   falling waveform, R_fixture 50.000Ohm, V_fixture 0: 20-80 % time 131ps typ, 139ps min, 110ps max; typ from 0.898 V to 0 V
[GND Clamp]
-1.48V    -1.923A    -2.185A    -1.768A
-1.145V   -724.9mA   -1.004A    -557.8mA
-1.098V   -564.4mA   -842.1mA   -400mA
-1.05V    -411.2mA   -684.6mA   -253.6mA
-1.002V   -269.9mA   -533mA     -130.2mA
-954.6mV  -149.3mA   -390.1mA   -52.62mA
-906.8mV  -64.83mA   -260.5mA   -27.54mA
-859.1mV  -26.07mA   -151.7mA   -21.41mA
-811.4mV  -14.62mA   -73.8mA    -17.99mA
-715.9mV  -8.247mA   -13.8mA    -12.04mA
-525mV    -1.646mA   -1.444mA   -2.745mA
2.959V    5.163nA    157.9nA    7.042nA
[Power Clamp]
-1.459V   2.086A     2.205A     2.044A
-1.173V   911.3mA    1.129A     779.1mA
-1.125V   725.7mA    956.4mA    581.8mA
-1.077V   546.8mA    787.6mA    395.5mA
-1.03V    378.5mA    624.4mA    230.1mA
-981.8mV  228.3mA    469.3mA    106.6mA
-934.1mV  110.5mA    326.5mA    43.38mA
-886.4mV  43.33mA    203mA      25.09mA
-838.6mV  20.28mA    108.4mA    20.04mA
-790.9mV  13.81mA    49.59mA    16.81mA
-647.7mV  6.615mA    6.928mA    8.547mA
2.98V     -9.151nA   -320.3nA   -14.09nA
[Pulldown]
-1.48V    -14.9mA    -7mA       -18mA
-1.241V   -19.2mA    -11.9mA    -21.3mA
-1.002V   -21.8mA    -16.7mA    -21.1mA
-811.4mV  -21.18mA   -19.64mA   -20.03mA
-668.2mV  -19.59mA   -20.07mA   -18.62mA
-381.8mV  -12.99mA   -13.57mA   -12.7mA
477.3mV   15.34mA    15.48mA    15.28mA
954.6mV   26.95mA    26.01mA    27.3mA
1.241V    30.97mA    29.06mA    31.74mA
1.623V    33.5mA     31.21mA    34.28mA
2.434V    35.5mA     32.8mA     36.55mA
2.959V    35.9mA     33.8mA     36.1mA
[Pullup]
-1.459V   19.1mA     13.41mA    20.91mA
-1.316V   20.8mA     15.5mA     21.9mA
-1.077V   21.8mA     18.74mA    21.11mA
-886.4mV  20.6mA     19.86mA    19.94mA
-695.5mV  18.61mA    18.6mA     18.09mA
-409.1mV  13.07mA    13.18mA    12.79mA
211.4mV   -6.618mA   -6.666mA   -6.541mA
640.9mV   -18.99mA   -18.94mA   -18.85mA
1.214V    -32.21mA   -31.33mA   -32.35mA
1.5V      -36.58mA   -34.84mA   -37.19mA
1.834V    -39.42mA   -36.93mA   -40.67mA
2.98V     -43.8mA    -40.56mA   -45.59mA
[Ramp]
R_load=50.000Ohm
dV/dt_r   544.170mV/124.500ps  518.549mV/133.000ps  569.040mV/116.000ps
dV/dt_f   544.170mV/113.000ps  518.549mV/123.500ps  569.040mV/108.000ps
[Rising waveform]
R_fixture=50.000Ohm
V_fixture=1.500
V_fixture_min=1.425
V_fixture_max=1.575
0s        583.7mV    550.6mV    615.9mV
1.327ns   583.7mV    550.6mV    615.9mV
1.429ns   583.8mV    550.6mV    741.2mV
1.531ns   583.4mV    550.7mV    1.304V
1.633ns   925.3mV    550.8mV    1.516V
1.735ns   1.351V     549.4mV    1.562V
1.837ns   1.466V     587.7mV    1.572V
2.042ns   1.498V     1.316V     1.575V
2.246ns   1.5V       1.419V     1.575V
10ns      1.5V       1.425V     1.575V
[Rising waveform]
R_fixture=50.000Ohm
V_fixture=0
0s        0V         1.817uV    0V
1.429ns   32.72uV    -4.446uV   -19.51mV
1.633ns   9.429mV    14.4uV     779.2mV
1.735ns   507mV      611.7uV    897.2mV
1.837ns   790.5mV    -12.94mV   926.7mV
1.939ns   869.6mV    77.96mV    934.7mV
2.042ns   889.7mV    530.5mV    937mV
2.144ns   895.3mV    759.8mV    937.5mV
2.348ns   897.5mV    846.1mV    937.7mV
10ns      897.6mV    854.1mV    937.7mV
[Falling waveform]
R_fixture=50.000Ohm
V_fixture=1.500
V_fixture_min=1.425
V_fixture_max=1.575
0s        1.5V       1.425V     1.575V
1.429ns   1.5V       1.425V     1.595V
1.633ns   1.438V     1.425V     755.6mV
1.735ns   921.3mV    1.424V     649.9mV
1.837ns   673.7mV    1.44V      624.9mV
1.939ns   607mV      1.267V     618.3mV
2.042ns   590.2mV    832.9mV    616.5mV
2.144ns   585.6mV    632.4mV    616.1mV
2.348ns   583.8mV    557.5mV    615.9mV
10ns      583.7mV    550.6mV    615.9mV
[Falling waveform]
R_fixture=50.000Ohm
V_fixture=0
0s        897.6mV    854.1mV    937.7mV
1.429ns   897.7mV    854.1mV    907.2mV
1.531ns   899.7mV    854.1mV    253.3mV
1.633ns   604.6mV    854.1mV    48.88mV
1.735ns   130.3mV    853.9mV    9.202mV
1.837ns   25.86mV    855.2mV    1.71mV
1.939ns   5.173mV    427.4mV    304.8uV
2.042ns   988.9uV    89.78mV    48.41uV
2.246ns   33.62uV    3.846mV    0V
10ns      0V         1.817uV    0V
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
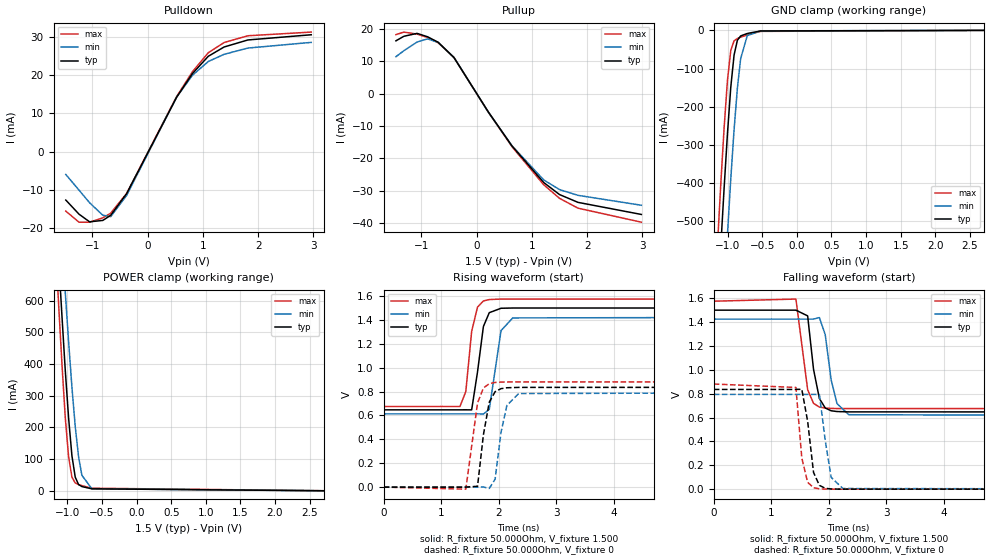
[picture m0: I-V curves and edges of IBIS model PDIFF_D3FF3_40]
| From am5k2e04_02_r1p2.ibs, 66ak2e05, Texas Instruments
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|   Model PDIFF_D3FF3_40
[Model] PDIFF_D3FF3_40
Model_type   I/O
Polarity   Non-Inverting
Enable   Active-High
C_comp   3.251pF   3.188pF   3.332pF
C_comp_pullup   516.830fF   493.667fF   544.031fF
C_comp_pulldown 2.728pF   2.688pF   2.782pF
Vinh = 925.000mV
Vinl = 575.000mV
Vmeas = 750.000mV
Vref = 750.000mV
Rref = 50Ohms
Cref = 0pF
[Model Spec]
Vinh   925.000mV   888.000mV   963.000mV
Vinl   575.000mV   538.000mV   613.000mV
Vmeas   750.000mV   713.000mV   788.000mV
Vref   750.000mV   713.000mV   788.000mV
[Temperature Range]   25.000   125.000   -40.000
[Voltage Range]   1.500V   1.425V   1.575V
[GND Clamp Reference]   0.00V   0.00V   0.00V
|[C Comp Corner]
| variable   typ   min   max
|C_comp 3.251pF   3.332pF   3.188pF
|C_comp_pullup 516.830fF   544.031fF   493.667fF
|C_comp_pulldown 2.728pF   2.782pF   2.688pF
[Pulldown Reference]   0.00V   0.00V   0.00V
[POWER Clamp Reference]   1.500V   1.425V   1.575V
[Pullup Reference]   1.500V   1.425V   1.575V
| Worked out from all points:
|   slope of the pulldown table from 0 to 0.225 V, typ, clamps not added: 34.8 ohm
|   slope of the pullup table from 0 to 0.225 V, typ, clamps not added: 37.5 ohm
|   GND clamp passes 1 mA (typ) near -0.49 V on its own axis
|   POWER clamp passes 1 mA (typ) near -0.46 V on its own axis
|   rising waveform, R_fixture 50.000Ohm, V_fixture 1.500: 20-80 % time 145ps typ, 154ps min, 136ps max; typ from 0.647 V to 1.5 V
|   rising waveform, R_fixture 50.000Ohm, V_fixture 0: 20-80 % time 150ps typ, 158ps min, 146ps max; typ from 0 V to 0.836 V
|   falling waveform, R_fixture 50.000Ohm, V_fixture 1.500: 20-80 % time 152ps typ, 166ps min, 148ps max; typ from 1.5 V to 0.647 V
|   falling waveform, R_fixture 50.000Ohm, V_fixture 0: 20-80 % time 134ps typ, 143ps min, 119ps max; typ from 0.836 V to 0 V
[GND Clamp]
-1.48V    -1.923A    -2.185A    -1.768A
-1.145V   -724.9mA   -1.004A    -557.8mA
-1.098V   -564.4mA   -842.1mA   -400mA
-1.05V    -411.2mA   -684.6mA   -253.6mA
-1.002V   -269.9mA   -533mA     -130.2mA
-954.6mV  -149.3mA   -390.1mA   -52.62mA
-906.8mV  -64.83mA   -260.5mA   -27.54mA
-859.1mV  -26.07mA   -151.7mA   -21.41mA
-811.4mV  -14.62mA   -73.8mA    -17.99mA
-715.9mV  -8.247mA   -13.8mA    -12.04mA
-525mV    -1.646mA   -1.444mA   -2.745mA
2.959V    5.164nA    157.9nA    7.042nA
[Power Clamp]
-1.459V   2.086A     2.205A     2.044A
-1.173V   911.3mA    1.129A     779.1mA
-1.125V   725.7mA    956.4mA    581.8mA
-1.077V   546.8mA    787.6mA    395.5mA
-1.03V    378.5mA    624.4mA    230.1mA
-981.8mV  228.3mA    469.3mA    106.6mA
-934.1mV  110.5mA    326.5mA    43.38mA
-886.4mV  43.33mA    203mA      25.09mA
-838.6mV  20.28mA    108.4mA    20.04mA
-790.9mV  13.81mA    49.59mA    16.81mA
-647.7mV  6.615mA    6.928mA    8.547mA
2.98V     -9.151nA   -320.3nA   -9.47nA
[Pulldown]
-1.48V    -12.7mA    -6mA       -15.6mA
-1.241V   -16.4mA    -10.1mA    -18.5mA
-1.05V    -18.4mA    -13.4mA    -18.5mA
-811.4mV  -18.04mA   -16.67mA   -17.37mA
-668.2mV  -16.7mA    -17.04mA   -16.14mA
-381.8mV  -11.07mA   -11.53mA   -11.01mA
525mV     14.24mA    14.27mA    14.43mA
811.4mV   20.45mA    20mA       20.93mA
1.098V    24.97mA    23.6mA     25.9mA
1.384V    27.4mA     25.48mA    28.57mA
1.814V    29.24mA    27.12mA    30.34mA
2.959V    30.6mA     28.6mA     31.3mA
[Pullup]
-1.459V   16.3mA     11.4mA     18.21mA
-1.316V   17.7mA     13.24mA    19mA
-1.077V   18.6mA     15.93mA    18.37mA
-886.4mV  17.55mA    16.9mA     17.34mA
-695.5mV  15.86mA    15.81mA    15.72mA
-409.1mV  11.14mA    11.2mA     11.13mA
211.4mV   -5.638mA   -5.669mA   -5.688mA
640.9mV   -16.18mA   -16.11mA   -16.39mA
1.214V    -27.44mA   -26.64mA   -28.13mA
1.5V      -31.16mA   -29.62mA   -32.33mA
1.834V    -33.57mA   -31.4mA    -35.36mA
2.98V     -37.3mA    -34.46mA   -39.69mA
[Ramp]
R_load=50.000Ohm
dV/dt_r   506.550mV/134.000ps  481.739mV/142.000ps  534.210mV/125.500ps
dV/dt_f   506.550mV/123.000ps  481.739mV/134.000ps  534.210mV/117.000ps
[Rising waveform]
R_fixture=50.000Ohm
V_fixture=1.500
V_fixture_min=1.425
V_fixture_max=1.575
0s        647.2mV    613.4mV    675.3mV
1.327ns   647.2mV    613.4mV    675.3mV
1.429ns   647.3mV    613.5mV    800.3mV
1.531ns   647mV      613.5mV    1.305V
1.633ns   965.7mV    613.6mV    1.508V
1.735ns   1.345V     612.1mV    1.559V
1.837ns   1.461V     651.4mV    1.571V
2.042ns   1.498V     1.311V     1.575V
2.246ns   1.5V       1.417V     1.575V
10ns      1.5V       1.425V     1.575V
[Rising waveform]
R_fixture=50.000Ohm
V_fixture=0
0s        0V         2.011uV    0V
1.429ns   26.63uV    -4.197uV   -17.23mV
1.633ns   6.979mV    13.32uV    704.1mV
1.735ns   437.8mV    547.9uV    830.2mV
1.837ns   711.5mV    -11.3mV    866.1mV
1.939ns   799.3mV    66.6mV     876.3mV
2.042ns   824.8mV    460.5mV    879.5mV
2.144ns   832.1mV    684.8mV    880.6mV
2.348ns   835.2mV    783.5mV    881mV
10ns      835.7mV    794.2mV    881mV
[Falling waveform]
R_fixture=50.000Ohm
V_fixture=1.500
V_fixture_min=1.425
V_fixture_max=1.575
0s        1.5V       1.425V     1.575V
1.429ns   1.5V       1.425V     1.593V
1.633ns   1.452V     1.425V     833.4mV
1.735ns   1.005V     1.425V     719.4mV
1.837ns   759.5mV    1.438V     687.9mV
1.939ns   680.2mV    1.294V     679.3mV
2.042ns   656.9mV    915.5mV    676.5mV
2.144ns   650.5mV    716.6mV    675.6mV
2.348ns   647.6mV    624mV      675.3mV
10ns      647.2mV    613.4mV    675.3mV
[Falling waveform]
R_fixture=50.000Ohm
V_fixture=0
0s        835.7mV    794.2mV    881mV
1.429ns   835.7mV    794.2mV    852.2mV
1.531ns   837.4mV    794.2mV    261.1mV
1.633ns   568.1mV    794.2mV    57.43mV
1.735ns   140.6mV    794.1mV    12.5mV
1.837ns   32.05mV    792.9mV    2.565mV
1.939ns   7.257mV    407.2mV    520.4uV
2.042ns   1.613mV    98.97mV    108.7uV
2.246ns   70.99uV    5.486mV    3.596uV
10ns      0V         2.012uV    0V
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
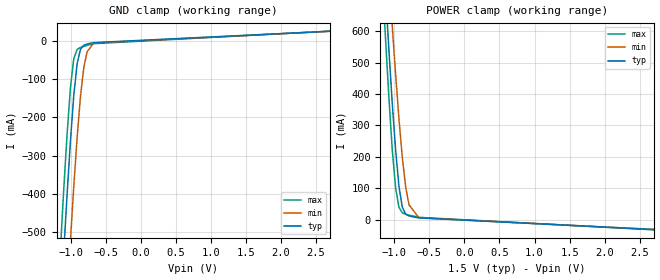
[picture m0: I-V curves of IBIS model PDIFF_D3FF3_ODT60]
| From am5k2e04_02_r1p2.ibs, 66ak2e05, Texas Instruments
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|   Model PDIFF_D3FF3_ODT60
[Model] PDIFF_D3FF3_ODT60
Model_type   Input
Polarity   Non-Inverting
Enable   Active-High
C_comp   3.300pF   3.240pF   3.401pF
C_comp_pullup   580.492fF   556.688fF   633.269fF
C_comp_pulldown 2.714pF   2.677pF   2.762pF
Vinh = 925.000mV
Vinl = 575.000mV
[Temperature Range]   25.000   125.000   -40.000
[Voltage Range]   1.500V   1.425V   1.575V
[GND Clamp Reference]   0.00V   0.00V   0.00V
|[C Comp Corner]
| variable   typ   min   max
|C_comp 3.300pF   3.401pF   3.240pF
|C_comp_pullup 580.492fF   633.269fF   556.688fF
|C_comp_pulldown 2.714pF   2.762pF   2.677pF
[POWER Clamp Reference]   1.500V   1.425V   1.575V
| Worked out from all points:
|   GND clamp passes 1 mA (typ) near -0.57 V on its own axis
|   POWER clamp passes 1 mA (typ) near -0.49 V on its own axis
[GND Clamp]
-1.48V    -1.907A    -2.167A    -1.752A
-1.145V   -715.8mA   -992.4mA   -548.7mA
-1.098V   -556.2mA   -831.7mA   -391.4mA
-1.05V    -403.8mA   -675.2mA   -245.8mA
-1.002V   -263.2mA   -524.6mA   -123mA
-954.6mV  -143.3mA   -382.7mA   -46.17mA
-906.8mV  -59.53mA   -254mA     -21.73mA
-859.1mV  -21.39mA   -146.1mA   -16.22mA
-811.4mV  -10.5mA    -69.05mA   -13.38mA
-763.6mV  -7.096mA   -27.31mA   -10.9mA
-668.2mV  -3.586mA   -4.602mA   -6.339mA
2.959V    28.5mA     28.55mA    29.03mA
[Power Clamp]
-1.459V   2.075A     2.193A     2.033A
-1.173V   904.6mA    1.121A     772.2mA
-1.125V   719.6mA    949.2mA    575.5mA
-1.077V   541.2mA    781.2mA    389.8mA
-1.03V    373.5mA    618.7mA    224.9mA
-981.8mV  223.8mA    464.2mA    101.9mA
-934.1mV  106.5mA    322.1mA    39.34mA
-886.4mV  39.87mA    199.2mA    21.57mA
-838.6mV  17.31mA    105.2mA    16.96mA
-790.9mV  11.27mA    46.97mA    14.15mA
-647.7mV  5.169mA    5.52mA     7.046mA
2.98V     -34.6mA    -34.72mA   -36.15mA
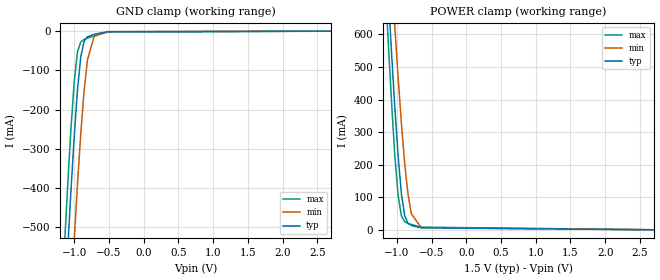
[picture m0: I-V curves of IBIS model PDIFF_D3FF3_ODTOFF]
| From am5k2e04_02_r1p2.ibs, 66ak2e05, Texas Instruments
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|   Model PDIFF_D3FF3_ODTOFF
[Model] PDIFF_D3FF3_ODTOFF
Model_type   Input
Polarity   Non-Inverting
Enable   Active-High
C_comp   3.251pF   3.188pF   3.332pF
C_comp_pullup   530.762fF   508.285fF   557.617fF
C_comp_pulldown 2.714pF   2.674pF   2.769pF
Vinh = 925.000mV
Vinl = 575.000mV
[Temperature Range]   25.000   125.000   -40.000
[Voltage Range]   1.500V   1.425V   1.575V
[GND Clamp Reference]   0.00V   0.00V   0.00V
|[C Comp Corner]
| variable   typ   min   max
|C_comp 3.251pF   3.332pF   3.188pF
|C_comp_pullup 530.762fF   557.617fF   508.285fF
|C_comp_pulldown 2.714pF   2.769pF   2.674pF
[POWER Clamp Reference]   1.500V   1.425V   1.575V
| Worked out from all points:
|   GND clamp passes 1 mA (typ) near -0.49 V on its own axis
|   POWER clamp passes 1 mA (typ) near -0.46 V on its own axis
[GND Clamp]
-1.48V    -1.923A    -2.185A    -1.768A
-1.145V   -724.9mA   -1.004A    -557.8mA
-1.098V   -564.4mA   -842.1mA   -400mA
-1.05V    -411.2mA   -684.6mA   -253.6mA
-1.002V   -269.9mA   -533mA     -130.2mA
-954.6mV  -149.3mA   -390.1mA   -52.62mA
-906.8mV  -64.83mA   -260.5mA   -27.54mA
-859.1mV  -26.07mA   -151.7mA   -21.41mA
-811.4mV  -14.62mA   -73.8mA    -17.99mA
-715.9mV  -8.247mA   -13.8mA    -12.04mA
-525mV    -1.646mA   -1.444mA   -2.745mA
2.959V    5.166nA    157.9nA    5.116nA
[Power Clamp]
-1.459V   2.086A     2.205A     2.044A
-1.173V   911.3mA    1.129A     779.1mA
-1.125V   725.7mA    956.4mA    581.8mA
-1.077V   546.8mA    787.6mA    395.5mA
-1.03V    378.5mA    624.4mA    230.1mA
-981.8mV  228.3mA    469.3mA    106.6mA
-934.1mV  110.5mA    326.5mA    43.38mA
-886.4mV  43.33mA    203mA      25.09mA
-838.6mV  20.28mA    108.4mA    20.04mA
-790.9mV  13.81mA    49.59mA    16.81mA
-647.7mV  6.615mA    6.928mA    8.547mA
2.98V     -9.151nA   -320.3nA   -2.398nA
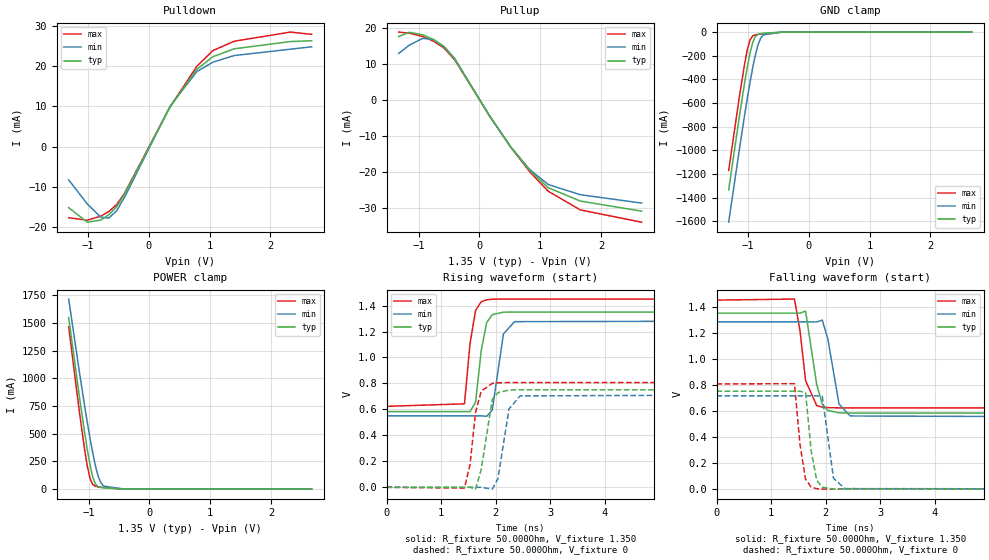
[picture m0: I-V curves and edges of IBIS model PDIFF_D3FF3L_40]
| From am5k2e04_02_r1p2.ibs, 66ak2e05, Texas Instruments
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|   Model PDIFF_D3FF3L_40
[Model] PDIFF_D3FF3L_40
Model_type   I/O
Polarity   Non-Inverting
Enable   Active-High
C_comp   3.258pF   3.193pF   3.341pF
C_comp_pullup   525.132fF   499.417fF   553.259fF
C_comp_pulldown 2.727pF   2.688pF   2.781pF
Vinh = 810.000mV
Vinl = 540.000mV
Vmeas = 675.000mV
Vref = 675.000mV
Rref = 50Ohms
Cref = 0pF
[Model Spec]
Vinh   810.000mV   777.000mV   860.000mV
Vinl   540.000mV   507.000mV   590.000mV
Vmeas   675.000mV   642.000mV   725.000mV
Vref   675.000mV   642.000mV   725.000mV
[Temperature Range]   25.000   125.000   -40.000
[Voltage Range]   1.350V   1.283V   1.450V
[GND Clamp Reference]   0.00V   0.00V   0.00V
|[C Comp Corner]
| variable   typ   min   max
|C_comp 3.258pF   3.341pF   3.193pF
|C_comp_pullup 525.132fF   553.259fF   499.417fF
|C_comp_pulldown 2.727pF   2.781pF   2.688pF
[Pulldown Reference]   0.00V   0.00V   0.00V
[POWER Clamp Reference]   1.350V   1.283V   1.450V
[Pullup Reference]   1.350V   1.283V   1.450V
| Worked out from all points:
|   slope of the pulldown table from 0 to 0.203 V, typ, clamps not added: 34.4 ohm
|   slope of the pullup table from 0 to 0.203 V, typ, clamps not added: 37.2 ohm
|   GND clamp passes 1 mA (typ) near -0.49 V on its own axis
|   POWER clamp passes 1 mA (typ) near -0.46 V on its own axis
|   rising waveform, R_fixture 50.000Ohm, V_fixture 1.350: 20-80 % time 149ps typ, 155ps min, 141ps max; typ from 0.583 V to 1.35 V
|   rising waveform, R_fixture 50.000Ohm, V_fixture 0: 20-80 % time 155ps typ, 165ps min, 152ps max; typ from 0 V to 0.752 V
|   falling waveform, R_fixture 50.000Ohm, V_fixture 1.350: 20-80 % time 171ps typ, 175ps min, 161ps max; typ from 1.35 V to 0.583 V
|   falling waveform, R_fixture 50.000Ohm, V_fixture 0: 20-80 % time 135ps typ, 143ps min, 135ps max; typ from 0.752 V to 0 V
[GND Clamp]
-1.318V   -1.335A    -1.608A    -1.171A
-1.142V   -714.5mA   -993.4mA   -547.6mA
-1.055V   -425.4mA   -699.4mA   -266.8mA
-1.011V   -293.4mA   -558.9mA   -149.2mA
-966.7mV  -177.2mA   -425.4mA   -66.61mA
-922.7mV  -87.91mA   -301.8mA   -32.11mA
-878.8mV  -37.17mA   -193.5mA   -23.26mA
-834.9mV  -18.49mA   -107.7mA   -19.59mA
-790.9mV  -12.57mA   -51.5mA    -16.66mA
-747mV    -9.759mA   -23.14mA   -13.91mA
-439.4mV  -371uA     -394.7uA   -656.8uA
2.68V     4.175nA    252.7nA    2.48nA
[Power Clamp]
-1.33V    1.55A      1.716A     1.465A
-1.155V   840mA      1.063A     702.7mA
-1.067V   508.3mA    750.7mA    355.3mA
-1.023V   355.7mA    601.6mA    207mA
-978.8mV  219.6mA    459.6mA    97.64mA
-934.9mV  112mA      328.4mA    43.17mA
-890.9mV  47.41mA    213.3mA    25.91mA
-847mV    22.45mA    121.8mA    20.7mA
-803mV    14.88mA    60.5mA     17.59mA
-759.1mV  11.72mA    27.97mA    14.84mA
-407.6mV  326.4uA    576.1uA    395.6uA
2.668V    -7.545nA   -288.5nA   181.4pA
[Pulldown]
-1.318V   -15.1mA    -8.2mA     -17.6mA
-1.011V   -18.7mA    -14.2mA    -18.2mA
-790.9mV  -18.16mA   -17.42mA   -17.2mA
-659.1mV  -16.89mA   -17.69mA   -16.07mA
-527.3mV  -14.85mA   -15.84mA   -14.31mA
-395.5mV  -11.68mA   -12.44mA   -11.43mA
351.5mV   9.878mA    10.1mA     9.93mA
790.9mV   19.22mA    18.65mA    19.95mA
1.055V    22.34mA    20.99mA    23.87mA
1.406V    24.3mA     22.63mA    26.18mA
2.329V    26.1mA     24.2mA     28.45mA
2.68V     26.3mA     24.8mA     27.9mA
[Pullup]
-1.33V    17.6mA     12.91mA    18.85mA
-1.155V   18.8mA     15.21mA    18.55mA
-934.9mV  18.1mA     17.11mA    17.61mA
-759.1mV  16.79mA    16.8mA     16.33mA
-583.3mV  14.75mA    14.85mA    14.4mA
-407.6mV  11.33mA    11.5mA     11.12mA
163.6mV   -4.425mA   -4.476mA   -4.406mA
515.1mV   -13.15mA   -13.16mA   -13.21mA
822.7mV   -19.62mA   -19.35mA   -19.95mA
1.13V     -24.46mA   -23.58mA   -25.44mA
1.658V    -28.18mA   -26.41mA   -30.65mA
2.668V    -31mA      -28.75mA   -34.07mA
[Ramp]
R_load=50.000Ohm
dV/dt_r   455.460mV/137.000ps  434.639mV/148.500ps  490.050mV/127.000ps
dV/dt_f   455.460mV/129.000ps  434.639mV/140.000ps  490.050mV/120.500ps
[Rising waveform]
R_fixture=50.000Ohm
V_fixture=1.350
V_fixture_min=1.283
V_fixture_max=1.450
0s        583.3mV    550.1mV    623.5mV
1.429ns   583.4mV    550.1mV    643mV
1.531ns   582.5mV    550.2mV    1.106V
1.633ns   656.2mV    550.2mV    1.363V
1.735ns   1.049V     550.2mV    1.429V
1.837ns   1.27V      547.1mV    1.445V
1.939ns   1.33V      595.2mV    1.449V
2.144ns   1.349V     1.182V     1.45V
2.348ns   1.35V      1.276V     1.45V
10ns      1.35V      1.283V     1.45V
[Rising waveform]
R_fixture=50.000Ohm
V_fixture=0
0s        0V         1.784uV    0V
1.429ns   -2.846uV   -2.306uV   -6.242mV
1.531ns   269.8uV    3.668uV    175.1mV
1.633ns   -14.43mV   -4.39uV    578.5mV
1.735ns   136.2mV    10.8uV     739.9mV
1.939ns   676.2mV    -14.34mV   800.8mV
2.042ns   728.9mV    64.89mV    805mV
2.246ns   749mV      603.8mV    806.8mV
2.45ns    751mV      704.1mV    807mV
10ns      751.5mV    715.9mV    807mV
[Falling waveform]
R_fixture=50.000Ohm
V_fixture=1.350
V_fixture_min=1.283
V_fixture_max=1.450
0s        1.35V      1.283V     1.45V
1.429ns   1.35V      1.283V     1.458V
1.531ns   1.35V      1.283V     1.214V
1.633ns   1.366V     1.283V     831.9mV
1.837ns   802.1mV    1.282V     641.1mV
1.939ns   651.9mV    1.297V     629mV
2.042ns   603.9mV    1.15V      625.3mV
2.246ns   585.7mV    652.8mV    623.6mV
2.45ns    583.6mV    561.4mV    623.5mV
10ns      583.3mV    550.1mV    623.5mV
[Falling waveform]
R_fixture=50.000Ohm
V_fixture=0
0s        751.5mV    715.9mV    807mV
1.429ns   751.5mV    715.9mV    809.2mV
1.531ns   751.3mV    715.9mV    339.7mV
1.633ns   739.6mV    715.9mV    75.99mV
1.735ns   294.7mV    715.8mV    16.54mV
1.837ns   68.11mV    716.2mV    3.577mV
1.939ns   15.46mV    711.5mV    726.1uV
2.144ns   779uV      85.1mV     29.34uV
2.348ns   33.24uV    4.655mV    0V
10ns      0V         1.781uV    0V
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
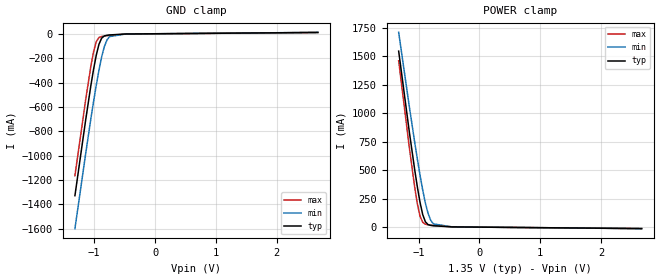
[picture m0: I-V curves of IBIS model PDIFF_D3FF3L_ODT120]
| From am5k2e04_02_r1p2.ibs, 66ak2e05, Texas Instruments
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|   Model PDIFF_D3FF3L_ODT120
[Model] PDIFF_D3FF3L_ODT120
Model_type   Input
Polarity   Non-Inverting
Enable   Active-High
C_comp   3.299pF   3.231pF   3.389pF
C_comp_pullup   570.327fF   542.003fF   611.937fF
C_comp_pulldown 2.722pF   2.683pF   2.771pF
Vinh = 810.000mV
Vinl = 540.000mV
[Temperature Range]   25.000   125.000   -40.000
[Voltage Range]   1.350V   1.283V   1.450V
[GND Clamp Reference]   0.00V   0.00V   0.00V
|[C Comp Corner]
| variable   typ   min   max
|C_comp 3.299pF   3.389pF   3.231pF
|C_comp_pullup 570.327fF   611.937fF   542.003fF
|C_comp_pulldown 2.722pF   2.771pF   2.683pF
[POWER Clamp Reference]   1.350V   1.283V   1.450V
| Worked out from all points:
|   GND clamp passes 1 mA (typ) near -0.52 V on its own axis
|   POWER clamp passes 1 mA (typ) near -0.47 V on its own axis
[GND Clamp]
-1.318V   -1.33A     -1.601A    -1.166A
-1.142V   -710.5mA   -987.9mA   -543.6mA
-1.055V   -422.1mA   -694.9mA   -263.3mA
-1.011V   -290.4mA   -554.9mA   -146mA
-966.7mV  -174.5mA   -421.7mA   -63.68mA
-922.7mV  -85.5mA    -298.6mA   -29.44mA
-878.8mV  -35.03mA   -190.7mA   -20.84mA
-834.9mV  -16.61mA   -105.4mA   -17.42mA
-790.9mV  -10.91mA   -49.54mA   -14.73mA
-747mV    -8.321mA   -21.54mA   -12.21mA
-483.3mV  -433.1uA   -454.7uA   -941.7uA
2.68V     12.19mA    12.74mA    12.09mA
[Power Clamp]
-1.33V    1.546A     1.711A     1.461A
-1.155V   836.9mA    1.059A     699.6mA
-1.067V   505.9mA    747.7mA    352.7mA
-1.023V   353.4mA    598.8mA    204.6mA
-978.8mV  217.6mA    457.2mA    95.5mA
-934.9mV  110.1mA    326.3mA    41.29mA
-890.9mV  45.82mA    211.4mA    24.26mA
-847mV    21.08mA    120.3mA    19.23mA
-803mV    13.7mA     59.24mA    16.31mA
-759.1mV  10.71mA    26.92mA    13.74mA
-451.5mV  690.9uA    1.017mA    894.5uA
2.668V    -14.07mA   -14.85mA   -14.48mA
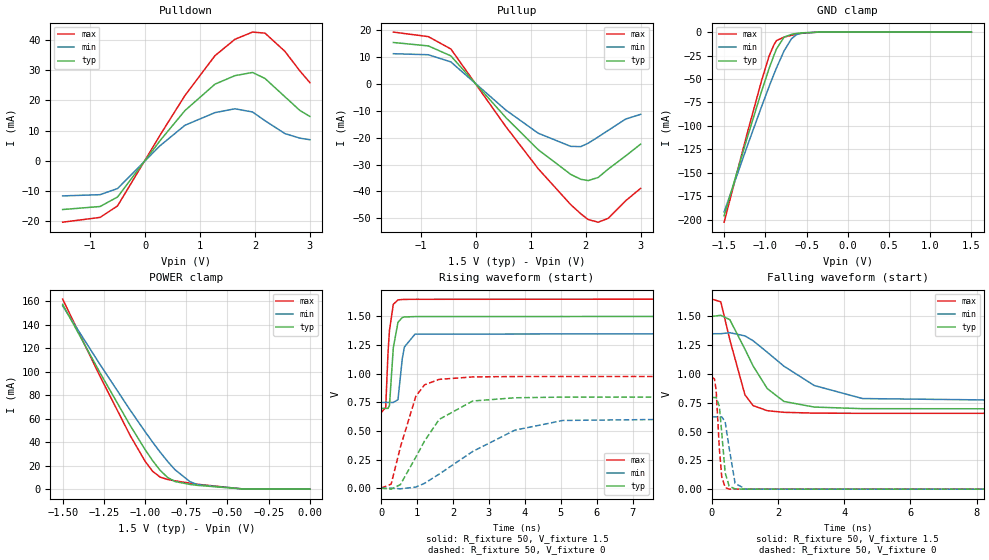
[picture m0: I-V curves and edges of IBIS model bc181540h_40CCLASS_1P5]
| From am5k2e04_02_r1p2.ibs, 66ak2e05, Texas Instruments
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|   Model Cell bc181540h_40CCLASS_1P5
|bc181540edc50bghypbfbh.ibs   [23Jan12 revision 1.0]
|bc181540h_40CCLASS_1P5
[Model]   bc181540h_40CCLASS_1P5
Model_type   I/O
Polarity   Non-Inverting
Enable   Active-Low
Vinl =  0.525
Vinh =  0.975
Cref =  15.0000pF
Rref =  100.0000M
Vref =  0V
Vmeas =  0.75
C_comp   1.17072p   0.570099p   1.17447p
[Model Spec]
Vinl   0.525   0.4725   0.5775
Vinh   0.975   0.8775   1.0725
[Temperature Range]   25   125   -40
[Voltage Range]   1.5   1.35   1.65
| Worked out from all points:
|   slope of the pulldown table from 0 to 0.225 V, typ, clamps not added: 40.7 ohm
|   slope of the pullup table from 0 to 0.225 V, typ, clamps not added: 42.7 ohm
|   GND clamp passes 1 mA (typ) near -0.58 V on its own axis
|   POWER clamp passes 1 mA (typ) near -0.52 V on its own axis
|   rising waveform, R_fixture 50, V_fixture 1.5: 20-80 % time 117ps typ, 135ps min, 103ps max; typ from 0.696 V to 1.5 V
|   rising waveform, R_fixture 50, V_fixture 0: 20-80 % time 941ps typ, 2.06ns min, 514ps max; typ from 0 V to 0.796 V
|   falling waveform, R_fixture 50, V_fixture 1.5: 20-80 % time 924ps typ, 1.84ns min, 519ps max; typ from 1.5 V to 0.696 V
|   falling waveform, R_fixture 50, V_fixture 0: 20-80 % time 136ps typ, 174ps min, 115ps max; typ from 0.796 V to 0 V
[POWER_clamp]
|   voltage   I(typ)   I(min)   I(max)
-1.5V     157.2mA    155.9mA    161.7mA
-1.273V   98.95mA    106mA      95.87mA
-1.091V   54.38mA    67.4mA     45.82mA
-1V       33.74mA    48.95mA    23.8mA
-954.5mV  24.35mA    40.1mA     15.29mA
-909.1mV  16.14mA    31.61mA    10.28mA
-863.6mV  9.975mA    23.68mA    8.252mA
-818.2mV  6.508mA    16.53mA    7.086mA
-727.3mV  4mA        6.353mA    5.092mA
-681.8mV  3.231mA    3.88mA     4.159mA
-409.1mV  177.3uA    258.7uA    224.6uA
0V        677pA      15.94nA    186.8pA
[Pulldown]
|   voltage   I(typ)   I(min)   I(max)
-1.5V     -16.18mA   -11.66mA   -20.38mA
-818.2mV  -15.18mA   -11.25mA   -18.79mA
-500mV    -12.01mA   -9.214mA   -14.96mA
272.7mV   6.67mA     4.988mA    8.497mA
727.3mV   16.67mA    11.78mA    21.68mA
1.273V    25.41mA    15.97mA    34.86mA
1.636V    28.23mA    17.24mA    40.29mA
1.955V    29.29mA    16.18mA    42.68mA
2.182V    27.31mA    13.3mA     42.34mA
2.545V    21.24mA    9.012mA    36.3mA
2.818V    16.68mA    7.5mA      29.79mA
3V        14.69mA    6.98mA     25.92mA
[Pullup]
|   voltage   I(typ)   I(min)   I(max)
-1.5V     15.42mA    11.25mA    19.29mA
-863.6mV  14.15mA    10.86mA    17.6mA
-454.5mV  10.44mA    8.203mA    13.01mA
545.5mV   -12.48mA   -9.696mA   -15.83mA
1.136V    -24.46mA   -18.33mA   -31.54mA
1.727V    -33.62mA   -23.21mA   -44.88mA
1.909V    -35.45mA   -23.32mA   -48.26mA
2.045V    -35.95mA   -22.05mA   -50.44mA
2.227V    -34.79mA   -19.71mA   -51.42mA
2.409V    -31.68mA   -17.28mA   -50.01mA
2.727V    -26.78mA   -13.06mA   -43.46mA
3V        -22.38mA   -11.31mA   -38.83mA
[GND_clamp]
|   voltage   I(typ)   I(min)   I(max)
-1.5V     -195.7mA   -191.7mA   -202.6mA
-1.227V   -114.7mA   -123.3mA   -110.1mA
-1.045V   -62.85mA   -79.19mA   -51.48mA
-954.5mV  -38.7mA    -58mA      -25.52mA
-893.9mV  -24.32mA   -44.5mA    -13.19mA
-863.6mV  -17.74mA   -37.93mA   -9.007mA
-772.7mV  -5.381mA   -20.03mA   -5.301mA
-681.8mV  -2.343mA   -6.948mA   -3.394mA
-621.2mV  -1.47mA    -2.783mA   -2.285mA
-560.6mV  -800.4uA   -1.037mA   -1.331mA
-348.5mV  -9.367uA   -19.45uA   -12.08uA
1.5V      677pA      908.2nA    87.75pA
[Ramp]
| variable   typ   min   max
dV/dt_f   0.490908/0.9345151n   0.367956/1.8592061n   0.602094/0.52287878n
dV/dt_r  0.4844256/0.94951981n 0.38166912/2.074778n   0.592713/0.51762016n
R_load = 50
[Rising Waveform]
R_fixture = 50
V_fixture = 1.5
V_fixture_min = 1.35
V_fixture_max = 1.65
|   time   V(typ)   V(min)   V(max)
0s        696.1mV    747.8mV    658.4mV
130.5ps   696.2mV    747.8mV    704.7mV
194.3ps   696mV      747.8mV    1.182V
234.1ps   720.3mV    747.8mV    1.374V
341ps     1.223V     747.8mV    1.604V
471.1ps   1.447V     772mV      1.643V
590.9ps   1.489V     1.13V      1.646V
650.5ps   1.494V     1.232V     1.647V
945ps     1.497V     1.344V     1.648V
16.71ns   1.5V       1.35V      1.65V
[Rising Waveform]
R_fixture = 50
V_fixture = 0
V_fixture_min = 0
V_fixture_max = 0
|   time   V(typ)   V(min)   V(max)
0s        0V         0V         0V
281.6ps   -8.785mV   0V         35.55mV
537.3ps   30.83mV    -5.966mV   357.2mV
970ps     272.4mV    9.802mV    804.1mV
1.21ns    411.6mV    42.36mV    901.7mV
1.616ns   599.9mV    122.6mV    949.2mV
2.547ns   760.4mV    320mV      970.5mV
3.719ns   788.6mV    506mV      974.1mV
5.056ns   794.5mV    590.8mV    974.4mV
16.74ns   795.9mV    627.8mV    974.5mV
[Falling Waveform]
R_fixture = 50
V_fixture = 1.5
V_fixture_min = 1.35
V_fixture_max = 1.65
|   time   V(typ)   V(min)   V(max)
0s        1.5V       1.35V      1.651V
273.2ps   1.51V      1.35V      1.627V
544.7ps   1.472V     1.359V     1.298V
1.003ns   1.215V     1.331V     818.8mV
1.249ns   1.07V      1.289V     725.6mV
1.678ns   873mV      1.189V     681.5mV
2.18ns    761.8mV    1.068V     667.4mV
3.094ns   713mV      900.4mV    660.4mV
4.555ns   699.1mV    786.9mV    658.6mV
16.71ns   696.1mV    747.8mV    658.4mV
[Falling Waveform]
R_fixture = 50
V_fixture = 0
V_fixture_min = 0
V_fixture_max = 0
|   time   V(typ)   V(min)   V(max)
0s        795.9mV    627.8mV    974.5mV
81.6ps    795.7mV    627.8mV    956.9mV
132.7ps   796.8mV    627.8mV    858.3mV
228.8ps   720.4mV    627.8mV    352.2mV
300.9ps   489.5mV    628.3mV    108.2mV
405ps     141.4mV    584.4mV    14.39mV
526.1ps   24.98mV    357.3mV    0V
705.5ps   2.668mV    49.71mV    0V
1.027ns   0V         0V         0V
16.74ns   0V         0V         0V
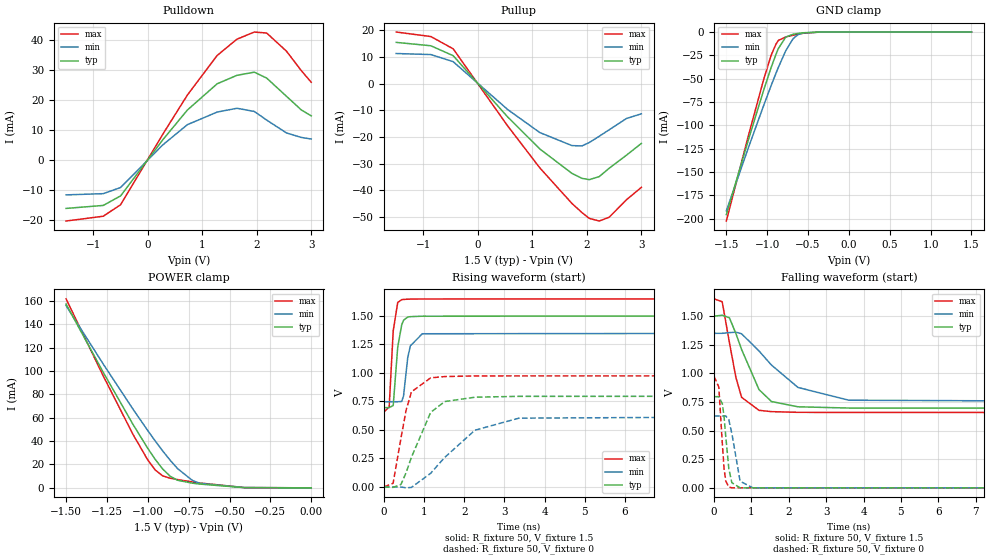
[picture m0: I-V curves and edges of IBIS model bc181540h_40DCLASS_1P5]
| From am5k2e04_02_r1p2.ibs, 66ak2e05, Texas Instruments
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|   Model Cell bc181540h_40DCLASS_1P5
|bc181540h_40DCLASS_1P5
[Model]   bc181540h_40DCLASS_1P5
Model_type   I/O
Polarity   Non-Inverting
Enable   Active-Low
Vinl =  0.525
Vinh =  0.975
Cref =  15.0000pF
Rref =  100.0000M
Vref =  0V
Vmeas =  0.75
C_comp   1.17072p   0.570099p   1.17447p
[Model Spec]
Vinl   0.525   0.4725   0.5775
Vinh   0.975   0.8775   1.0725
[Temperature Range]   25   125   -40
[Voltage Range]   1.5   1.35   1.65
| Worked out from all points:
|   slope of the pulldown table from 0 to 0.225 V, typ, clamps not added: 40.7 ohm
|   slope of the pullup table from 0 to 0.225 V, typ, clamps not added: 42.7 ohm
|   GND clamp passes 1 mA (typ) near -0.58 V on its own axis
|   POWER clamp passes 1 mA (typ) near -0.52 V on its own axis
|   rising waveform, R_fixture 50, V_fixture 1.5: 20-80 % time 117ps typ, 136ps min, 97.6ps max; typ from 0.696 V to 1.5 V
|   rising waveform, R_fixture 50, V_fixture 0: 20-80 % time 544ps typ, 1.11ns min, 313ps max; typ from 0 V to 0.796 V
|   falling waveform, R_fixture 50, V_fixture 1.5: 20-80 % time 611ps typ, 1.19ns min, 348ps max; typ from 1.5 V to 0.696 V
|   falling waveform, R_fixture 50, V_fixture 0: 20-80 % time 136ps typ, 175ps min, 108ps max; typ from 0.796 V to 0 V
[POWER_clamp]
|   voltage   I(typ)   I(min)   I(max)
-1.5V     157.2mA    155.9mA    161.7mA
-1.273V   98.95mA    106mA      95.87mA
-1.091V   54.38mA    67.4mA     45.82mA
-1V       33.74mA    48.95mA    23.8mA
-954.5mV  24.35mA    40.1mA     15.29mA
-909.1mV  16.14mA    31.61mA    10.28mA
-863.6mV  9.975mA    23.68mA    8.252mA
-818.2mV  6.508mA    16.53mA    7.086mA
-727.3mV  4mA        6.353mA    5.092mA
-681.8mV  3.231mA    3.88mA     4.159mA
-409.1mV  177.3uA    258.7uA    224.6uA
0V        677pA      15.94nA    186.8pA
[Pulldown]
|   voltage   I(typ)   I(min)   I(max)
-1.5V     -16.18mA   -11.66mA   -20.38mA
-818.2mV  -15.18mA   -11.25mA   -18.79mA
-500mV    -12.01mA   -9.214mA   -14.96mA
272.7mV   6.67mA     4.988mA    8.497mA
727.3mV   16.67mA    11.78mA    21.68mA
1.273V    25.41mA    15.97mA    34.86mA
1.636V    28.23mA    17.24mA    40.29mA
1.955V    29.29mA    16.18mA    42.68mA
2.182V    27.31mA    13.3mA     42.34mA
2.545V    21.24mA    9.012mA    36.3mA
2.818V    16.68mA    7.5mA      29.79mA
3V        14.69mA    6.98mA     25.92mA
[Pullup]
|   voltage   I(typ)   I(min)   I(max)
-1.5V     15.42mA    11.25mA    19.29mA
-863.6mV  14.15mA    10.86mA    17.6mA
-454.5mV  10.44mA    8.203mA    13.01mA
545.5mV   -12.48mA   -9.696mA   -15.83mA
1.136V    -24.46mA   -18.33mA   -31.54mA
1.727V    -33.62mA   -23.21mA   -44.88mA
1.909V    -35.45mA   -23.32mA   -48.26mA
2.045V    -35.95mA   -22.05mA   -50.44mA
2.227V    -34.79mA   -19.71mA   -51.42mA
2.409V    -31.68mA   -17.28mA   -50.01mA
2.727V    -26.78mA   -13.06mA   -43.46mA
3V        -22.38mA   -11.31mA   -38.83mA
[GND_clamp]
|   voltage   I(typ)   I(min)   I(max)
-1.5V     -195.7mA   -191.7mA   -202.6mA
-1.227V   -114.7mA   -123.3mA   -110.1mA
-1.045V   -62.85mA   -79.19mA   -51.48mA
-954.5mV  -38.7mA    -58mA      -25.52mA
-893.9mV  -24.32mA   -44.5mA    -13.19mA
-863.6mV  -17.74mA   -37.93mA   -9.007mA
-772.7mV  -5.381mA   -20.03mA   -5.301mA
-681.8mV  -2.343mA   -6.948mA   -3.394mA
-621.2mV  -1.47mA    -2.783mA   -2.285mA
-560.6mV  -800.4uA   -1.037mA   -1.331mA
-348.5mV  -9.367uA   -19.45uA   -12.08uA
1.5V      677pA      908.2nA    87.75pA
[Ramp]
| variable   typ   min   max
dV/dt_f   0.488688/0.61647312n   0.367416/1.1968839n   0.601014/0.35044236n
dV/dt_r   0.484689/0.5488938n 0.38195178/1.1220466n  0.5910444/0.31497044n
R_load = 50
[Rising Waveform]
R_fixture = 50
V_fixture = 1.5
V_fixture_min = 1.35
V_fixture_max = 1.65
|   time   V(typ)   V(min)   V(max)
0s        696.1mV    747.8mV    658.4mV
130.2ps   696.2mV    747.8mV    702.1mV
230.9ps   714.9mV    747.8mV    1.369V
342.5ps   1.225V     747.8mV    1.618V
442.1ps   1.422V     749.9mV    1.643V
487.9ps   1.462V     798.1mV    1.645V
592.2ps   1.491V     1.133V     1.647V
657.6ps   1.494V     1.238V     1.648V
956.7ps   1.498V     1.344V     1.649V
16.71ns   1.5V       1.35V      1.65V
[Rising Waveform]
R_fixture = 50
V_fixture = 0
V_fixture_min = 0
V_fixture_max = 0
|   time   V(typ)   V(min)   V(max)
0s        0V         0V         0V
228.7ps   -3.367mV   0V         32.64mV
422.2ps   21.52mV    0V         425.1mV
552.7ps   126.1mV    -7.552mV   674mV
685.4ps   261.8mV    -3.633mV   834.7mV
1.164ns   654.4mV    120.5mV    957.1mV
1.515ns   749.5mV    259.9mV    968.7mV
2.267ns   787.5mV    497.9mV    973.8mV
3.359ns   795mV      603.7mV    974.5mV
16.74ns   795.9mV    627.8mV    974.5mV
[Falling Waveform]
R_fixture = 50
V_fixture = 1.5
V_fixture_min = 1.35
V_fixture_max = 1.65
|   time   V(typ)   V(min)   V(max)
0s        1.5V       1.35V      1.651V
217.1ps   1.508V     1.35V      1.626V
410.1ps   1.486V     1.356V     1.27V
583ps     1.349V     1.36V      966.1mV
736ps     1.209V     1.346V     791mV
1.202ns   858.4mV    1.196V     677.2mV
1.535ns   754.3mV    1.073V     665.8mV
2.244ns   708.1mV    877.3mV    659.7mV
3.608ns   697.2mV    765.5mV    658.5mV
16.71ns   696.1mV    747.8mV    658.4mV
[Falling Waveform]
R_fixture = 50
V_fixture = 0
V_fixture_min = 0
V_fixture_max = 0
|   time   V(typ)   V(min)   V(max)
0s        795.9mV    627.8mV    974.5mV
127ps     796.8mV    627.8mV    880.3mV
222.1ps   734mV      627.8mV    380.5mV
265.8ps   625.3mV    627.7mV    174.6mV
311.9ps   451.6mV    628.4mV    59.99mV
395ps     165.8mV    594.5mV    7.939mV
476.4ps   44.61mV    474.5mV    0V
696.7ps   0V         57.6mV     0V
1.041ns   0V         0V         0V
16.74ns   0V         0V         0V
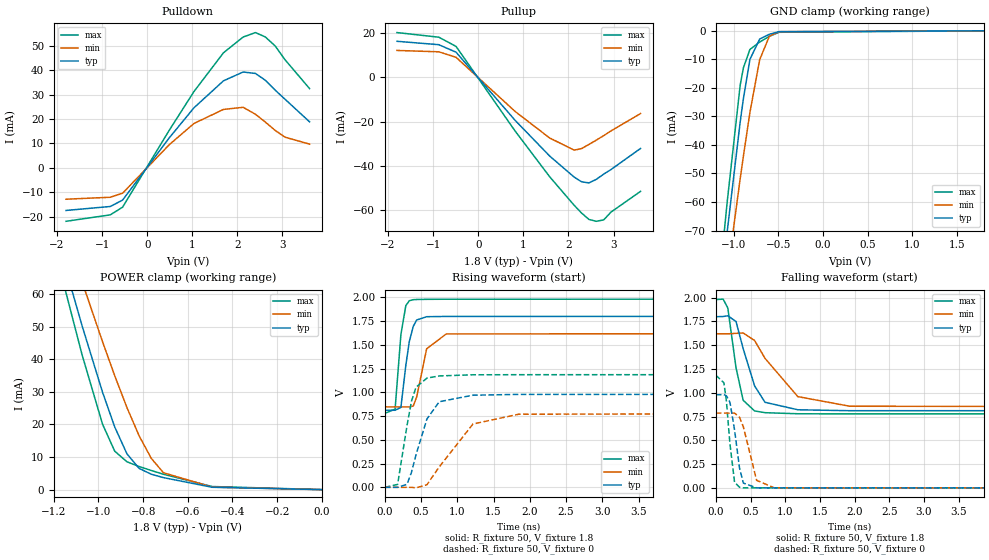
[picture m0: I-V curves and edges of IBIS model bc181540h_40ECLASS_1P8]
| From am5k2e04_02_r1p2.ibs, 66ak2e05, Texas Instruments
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|   Model Cell bc181540h_40ECLASS_1P8
|bc181540h_40ECLASS_1P8
[Model]   bc181540h_40ECLASS_1P8
Model_type   I/O
Polarity   Non-Inverting
Enable   Active-Low
Vinl =  0.63
Vinh =  1.17
Cref =  15.0000pF
Rref =  100.0000M
Vref =  0V
Vmeas =  0.9
C_comp   1.16613p   0.553312p   1.16742p
[Model Spec]
Vinl   0.63   0.567   0.693
Vinh   1.17   1.053   1.287
[Temperature Range]   25   125   -40
[Voltage Range]   1.8   1.62   1.98
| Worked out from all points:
|   slope of the pulldown table from 0 to 0.27 V, typ, clamps not added: 39.2 ohm
|   slope of the pullup table from 0 to 0.27 V, typ, clamps not added: 40.9 ohm
|   GND clamp passes 1 mA (typ) near -0.58 V on its own axis
|   POWER clamp passes 1 mA (typ) near -0.52 V on its own axis
|   rising waveform, R_fixture 50, V_fixture 1.8: 20-80 % time 101ps typ, 130ps min, 76.8ps max; typ from 0.811 V to 1.8 V
|   rising waveform, R_fixture 50, V_fixture 0: 20-80 % time 239ps typ, 442ps min, 152ps max; typ from 0 V to 0.979 V
|   falling waveform, R_fixture 50, V_fixture 1.8: 20-80 % time 250ps typ, 470ps min, 147ps max; typ from 1.8 V to 0.811 V
|   falling waveform, R_fixture 50, V_fixture 0: 20-80 % time 107ps typ, 146ps min, 83.8ps max; typ from 0.979 V to 0 V
[POWER_clamp]
|   voltage   I(typ)   I(min)   I(max)
-1.8V     235.9mA    223mA      250.7mA
-1.164V   71.87mA    82.65mA    65.36mA
-1.127V   63.07mA    75mA       55.51mA
-1.073V   50.17mA    63.68mA    41.25mA
-981.8mV  29.88mA    45.37mA    20.07mA
-927.3mV  19.23mA    34.95mA    11.8mA
-872.7mV  11mA       25.21mA    8.54mA
-818.2mV  6.508mA    16.53mA    7.086mA
-763.6mV  4.722mA    9.611mA    5.869mA
-709.1mV  3.682mA    5.172mA    4.713mA
-490.9mV  715.9uA    765.4uA    948.8uA
0V        973.6pA    18.39nA    2.408nA
[Pulldown]
|   voltage   I(typ)   I(min)   I(max)
-1.8V     -17.49mA   -12.88mA   -21.94mA
-818.2mV  -15.86mA   -12.08mA   -19.3mA
-545.5mV  -13.25mA   -10.42mA   -16.15mA
490.9mV   12.32mA    9.498mA    15.44mA
1.036V    24.59mA    18.17mA    31.25mA
1.691V    35.67mA    23.94mA    47.16mA
2.127V    39.29mA    24.81mA    53.62mA
2.4V      38.7mA     21.96mA    55.46mA
2.618V    35.92mA    18.78mA    53.67mA
2.836V    31.87mA    15.36mA    50.01mA
3.055V    28.14mA    12.57mA    44.34mA
3.6V      18.85mA    9.7mA      32.48mA
[Pullup]
|   voltage   I(typ)   I(min)   I(max)
-1.8V     16.38mA    12.23mA    20.34mA
-872.7mV  14.84mA    11.61mA    18.24mA
-490.9mV  11.44mA    9.116mA    14.06mA
818.2mV   -19.46mA   -15.43mA   -24.31mA
1.582V    -35.6mA    -27.44mA   -44.98mA
2.127V    -45.2mA    -32.99mA   -57.98mA
2.291V    -47.33mA   -32.3mA    -61.49mA
2.455V    -47.84mA   -30.39mA   -64.41mA
2.618V    -46.24mA   -28.46mA   -65.26mA
2.782V    -43.87mA   -26.41mA   -64.63mA
2.945V    -41.78mA   -24.25mA   -61.08mA
3.6V      -32.22mA   -16.39mA   -51.67mA
[GND_clamp]
|   voltage   I(typ)   I(min)   I(max)
-1.8V     -286.5mA   -268.3mA   -306.4mA
-1.182V   -101.5mA   -112.2mA   -95.12mA
-1.145V   -91mA      -103.2mA   -83.18mA
-1.109V   -80.68mA   -94.46mA   -71.51mA
-1.073V   -70.47mA   -85.72mA   -60.02mA
-927.3mV  -31.93mA   -51.83mA   -19.01mA
-890.9mV  -23.7mA    -43.85mA   -12.93mA
-818.2mV  -10.01mA   -28.59mA   -6.521mA
-709.1mV  -2.875mA   -10.12mA   -3.938mA
-600mV    -1.201mA   -1.844mA   -1.918mA
-490.9mV  -279uA     -308.3uA   -510uA
1.8V      973.6pA    1.906uA    493.4pA
[Ramp]
| variable   typ   min   max
dV/dt_f   0.599538/0.25163865n   0.469398/0.47269164n   0.727914/0.14752256n
dV/dt_r 0.59186376/0.24018283n 0.47778552/0.4453348n 0.71513388/0.15225177n
R_load = 50
[Rising Waveform]
R_fixture = 50
V_fixture = 1.8
V_fixture_min = 1.62
V_fixture_max = 1.98
|   time   V(typ)   V(min)   V(max)
0s        810.7mV    846.4mV    777.9mV
141.6ps   810.8mV    846.4mV    822.5mV
221.6ps   840.4mV    846.3mV    1.606V
289.4ps   1.282V     846.4mV    1.911V
337.2ps   1.533V     845.8mV    1.963V
392.5ps   1.694V     855.8mV    1.974V
440.1ps   1.761V     952.4mV    1.976V
577.1ps   1.795V     1.458V     1.978V
847.5ps   1.798V     1.614V     1.979V
16.71ns   1.8V       1.62V      1.98V
[Rising Waveform]
R_fixture = 50
V_fixture = 0
V_fixture_min = 0
V_fixture_max = 0
|   time   V(typ)   V(min)   V(max)
0s        0V         0V         0V
176.3ps   0V         0V         30.53mV
306.1ps   31.86mV    0V         651mV
367.5ps   158.1mV    0V         905.5mV
429.5ps   340.6mV    -5.609mV   1.052V
580.3ps   717.9mV    26.9mV     1.149V
750.5ps   900.8mV    215.1mV    1.172V
1.216ns   969.3mV    666.3mV    1.184V
1.848ns   977.8mV    769.4mV    1.185V
16.75ns   978.8mV    786.4mV    1.185V
[Falling Waveform]
R_fixture = 50
V_fixture = 1.8
V_fixture_min = 1.62
V_fixture_max = 1.98
|   time   V(typ)   V(min)   V(max)
0s        1.8V       1.62V      1.98V
105.4ps   1.802V     1.62V      1.985V
172.5ps   1.81V      1.62V      1.892V
290.7ps   1.75V      1.625V     1.264V
393.3ps   1.465V     1.629V     921.6mV
558.2ps   1.073V     1.55V      809.2mV
708.7ps   899.8mV    1.362V     790.6mV
1.181ns   821.3mV    959.7mV    779.4mV
1.93ns    811.5mV    858.5mV    778mV
16.71ns   810.7mV    846.4mV    777.9mV
[Falling Waveform]
R_fixture = 50
V_fixture = 0
V_fixture_min = 0
V_fixture_max = 0
|   time   V(typ)   V(min)   V(max)
0s        978.8mV    786.4mV    1.185V
116.4ps   980.5mV    786.4mV    1.105V
151.8ps   968.4mV    786.5mV    916.3mV
203.6ps   900.3mV    786.2mV    460.5mV
269.9ps   608.5mV    786mV      59.26mV
341.2ps   209mV      741.8mV    5.876mV
396.6ps   50.22mV    642.1mV    0V
587.6ps   0V         79.08mV    0V
844.5ps   0V         0V         0V
16.75ns   0V         0V         0V
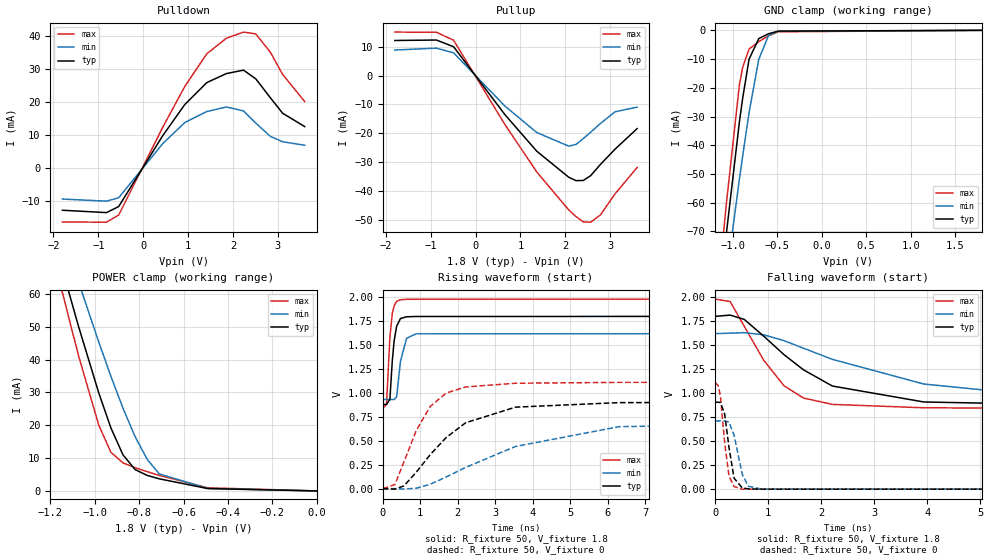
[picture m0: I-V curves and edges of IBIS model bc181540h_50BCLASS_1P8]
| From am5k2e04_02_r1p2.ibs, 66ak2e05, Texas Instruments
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|   Model Cell bc181540h_50BCLASS_1P8
|bc181540h_50BCLASS_1P8
[Model]   bc181540h_50BCLASS_1P8
Model_type   I/O
Polarity   Non-Inverting
Enable   Active-Low
Vinl =  0.63
Vinh =  1.17
Cref =  15.0000pF
Rref =  100.0000M
Vref =  0V
Vmeas =  0.9
C_comp   1.16613p   0.553312p   1.16742p
[Model Spec]
Vinl   0.63   0.567   0.693
Vinh   1.17   1.053   1.287
[Temperature Range]   25   125   -40
[Voltage Range]   1.8   1.62   1.98
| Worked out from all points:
|   slope of the pulldown table from 0 to 0.27 V, typ, clamps not added: 43.8 ohm
|   slope of the pullup table from 0 to 0.27 V, typ, clamps not added: 47 ohm
|   GND clamp passes 1 mA (typ) near -0.58 V on its own axis
|   POWER clamp passes 1 mA (typ) near -0.52 V on its own axis
|   rising waveform, R_fixture 50, V_fixture 1.8: 20-80 % time 114ps typ, 133ps min, 100ps max; typ from 0.879 V to 1.8 V
|   rising waveform, R_fixture 50, V_fixture 0: 20-80 % time 1.46ns typ, 2.99ns min, 823ps max; typ from 0 V to 0.906 V
|   falling waveform, R_fixture 50, V_fixture 1.8: 20-80 % time 1.38ns typ, 2.62ns min, 818ps max; typ from 1.8 V to 0.879 V
|   falling waveform, R_fixture 50, V_fixture 0: 20-80 % time 131ps typ, 162ps min, 116ps max; typ from 0.906 V to 0 V
[POWER_clamp]
|   voltage   I(typ)   I(min)   I(max)
-1.8V     235.9mA    223mA      250.7mA
-1.164V   71.87mA    82.65mA    65.36mA
-1.127V   63.07mA    75mA       55.51mA
-1.073V   50.17mA    63.68mA    41.25mA
-981.8mV  29.88mA    45.37mA    20.07mA
-927.3mV  19.23mA    34.95mA    11.8mA
-872.7mV  11mA       25.21mA    8.54mA
-818.2mV  6.508mA    16.53mA    7.086mA
-763.6mV  4.722mA    9.611mA    5.869mA
-709.1mV  3.682mA    5.172mA    4.713mA
-490.9mV  715.9uA    765.4uA    948.8uA
0V        973.6pA    18.39nA    2.408nA
[Pulldown]
|   voltage   I(typ)   I(min)   I(max)
-1.8V     -12.89mA   -9.49mA    -16.46mA
-818.2mV  -13.61mA   -10.13mA   -16.52mA
-545.5mV  -11.77mA   -9.098mA   -14.35mA
436.4mV   9.765mA    7.352mA    12.31mA
927.3mV   19.21mA    13.73mA    24.7mA
1.418V    25.88mA    17.08mA    34.64mA
1.855V    28.62mA    18.48mA    39.36mA
2.236V    29.66mA    17.28mA    41.22mA
2.509V    27.03mA    13.58mA    40.68mA
2.836V    21.25mA    9.531mA    35.08mA
3.109V    16.56mA    7.91mA     28.35mA
3.6V      12.52mA    6.85mA     20.12mA
[Pullup]
|   voltage   I(typ)   I(min)   I(max)
-1.8V     12.1mA     8.81mA     15mA
-872.7mV  12.26mA    9.455mA    14.95mA
-490.9mV  9.947mA    7.835mA    12.2mA
654.5mV   -13.53mA   -10.57mA   -16.96mA
1.364V    -26.15mA   -19.69mA   -33.32mA
2.073V    -35.09mA   -24.37mA   -46.38mA
2.236V    -36.3mA    -23.82mA   -48.69mA
2.4V      -36.24mA   -21.76mA   -50.56mA
2.564V    -34.58mA   -19.59mA   -50.65mA
2.782V    -30.7mA    -16.56mA   -48.14mA
3.109V    -25.41mA   -12.51mA   -40.82mA
3.6V      -18.33mA   -10.91mA   -31.77mA
[GND_clamp]
|   voltage   I(typ)   I(min)   I(max)
-1.8V     -286.5mA   -268.3mA   -306.4mA
-1.182V   -101.5mA   -112.2mA   -95.12mA
-1.145V   -91mA      -103.2mA   -83.18mA
-1.109V   -80.68mA   -94.46mA   -71.51mA
-1.073V   -70.47mA   -85.72mA   -60.02mA
-927.3mV  -31.93mA   -51.83mA   -19.01mA
-890.9mV  -23.7mA    -43.85mA   -12.93mA
-818.2mV  -10.01mA   -28.59mA   -6.521mA
-709.1mV  -2.875mA   -10.12mA   -3.938mA
-600mV    -1.201mA   -1.844mA   -1.918mA
-490.9mV  -279uA     -308.3uA   -510uA
1.8V      973.6pA    1.906uA    493.4pA
[Ramp]
| variable   typ   min   max
dV/dt_f   0.560502/1.3873042n   0.419574/2.6336992n   0.690516/0.82216276n
dV/dt_r 0.54926328/1.4692691n 0.43105314/2.9997915n  0.6734688/0.82577803n
R_load = 50
[Rising Waveform]
R_fixture = 50
V_fixture = 1.8
V_fixture_min = 1.62
V_fixture_max = 1.98
|   time   V(typ)   V(min)   V(max)
0s        879.4mV    931.1mV    842.9mV
100.7ps   879.5mV    931.1mV    878.6mV
191ps     932.3mV    931mV      1.577V
254.6ps   1.331V     931.2mV    1.827V
303.6ps   1.542V     930.5mV    1.911V
372.1ps   1.697V     960.3mV    1.957V
473.5ps   1.777V     1.331V     1.973V
636.8ps   1.795V     1.57V      1.977V
888.8ps   1.798V     1.617V     1.978V
16.75ns   1.8V       1.62V      1.98V
[Rising Waveform]
R_fixture = 50
V_fixture = 0
V_fixture_min = 0
V_fixture_max = 0
|   time   V(typ)   V(min)   V(max)
0s        0V         0V         0V
324.7ps   -5.098mV   0V         42.74mV
566.8ps   29.56mV    -3.214mV   280.2mV
893.6ps   171.4mV    4.617mV    606.1mV
1.266ns   354.6mV    46.09mV    858mV
1.69ns    533.5mV    121.6mV    998.2mV
2.211ns   688mV      221.8mV    1.062V
3.54ns    851.2mV    440.7mV    1.101V
6.304ns   898.7mV    647.5mV    1.11V
16.71ns   905.8mV    710.9mV    1.111V
[Falling Waveform]
R_fixture = 50
V_fixture = 1.8
V_fixture_min = 1.62
V_fixture_max = 1.98
|   time   V(typ)   V(min)   V(max)
0s        1.8V       1.62V      1.98V
282.3ps   1.813V     1.625V     1.954V
548.6ps   1.768V     1.63V      1.696V
912.8ps   1.595V     1.608V     1.345V
1.297ns   1.401V     1.547V     1.077V
1.665ns   1.243V     1.468V     949mV
2.21ns    1.074V     1.352V     882.9mV
3.934ns   908.1mV    1.095V     847.6mV
6.162ns   884.3mV    972.4mV    843mV
16.75ns   879.4mV    931.1mV    842.4mV
[Falling Waveform]
R_fixture = 50
V_fixture = 0
V_fixture_min = 0
V_fixture_max = 0
|   time   V(typ)   V(min)   V(max)
0s        905.8mV    710.9mV    1.111V
57.9ps    905.6mV    710.9mV    1.078V
100.4ps   901.8mV    710.9mV    963.1mV
179ps     783.1mV    710.6mV    485.1mV
260.7ps   434.8mV    699.9mV    137.1mV
356.5ps   114.5mV    562.6mV    26.65mV
511.2ps   12.58mV    152.3mV    0V
628ps     2.896mV    29.61mV    0V
886.8ps   0V         0V         0V
16.71ns   0V         0V         0V
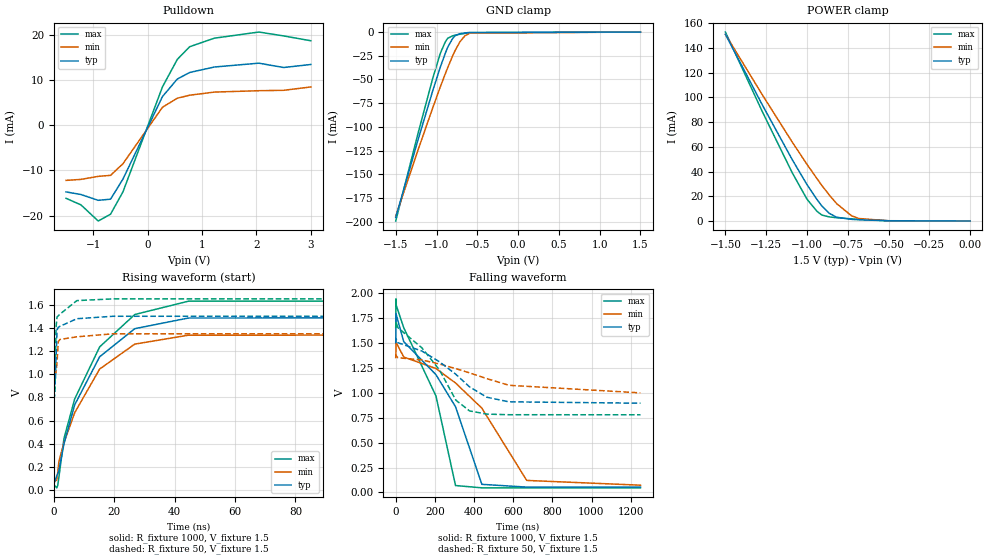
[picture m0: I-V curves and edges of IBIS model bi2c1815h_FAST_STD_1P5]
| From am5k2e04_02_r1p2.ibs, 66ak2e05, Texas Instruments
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|   Model Cell bi2c1815h_FAST_STD_1P5
|bi2c1815h_FAST_STD_1P5
[Model]   bi2c1815h_FAST_STD_1P5
Model_type   I/O_open_drain
Polarity   Non-Inverting
Enable   Active-Low
Vinl =  0.45
Vinh =  1.05
Cref =  15.0000pF
Rref =  100.0000M
Vref =  1.5
Vmeas =  0.75
C_comp   7.63862p   2.44169p   8.22121p
[Model Spec]
Vinl   0.45   0.405   0.495
Vinh   1.05   0.945   1.155
[Temperature Range]   25   125   -40
[Voltage Range]   1.5   1.35   1.65
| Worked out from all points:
|   slope of the pulldown table from 0 to 0.225 V, typ, clamps not added: 41.5 ohm
|   GND clamp passes 1 mA (typ) near -0.66 V on its own axis
|   POWER clamp passes 1 mA (typ) near -0.68 V on its own axis
|   rising waveform, R_fixture 1000, V_fixture 1.5: 20-80 % time 14.2ns typ, 14.6ns min, 15.2ns max; typ from 0.054 V to 1.5 V
|   rising waveform, R_fixture 50, V_fixture 1.5: 20-80 % time 428ps typ, 488ps min, 413ps max; typ from 0.894 V to 1.5 V
|   falling waveform, R_fixture 1000, V_fixture 1.5: 20-80 % time 191ns typ, 285ns min, 143ns max; typ from 1.5 V to 0.054 V
|   falling waveform, R_fixture 50, V_fixture 1.5: 20-80 % time 239ns typ, 352ns min, 176ns max; typ from 1.5 V to 0.894 V
[POWER_clamp]
|   voltage   I(typ)   I(min)   I(max)
-1.5V     151mA      150.9mA    152.8mA
-1.273V   93.69mA    101.9mA    88.24mA
-1.091V   49.77mA    63.93mA    39.17mA
-1V       29.43mA    45.82mA    17.67mA
-939.4mV  17.53mA    34.37mA    7.927mA
-909.1mV  12.18mA    28.82mA    4.843mA
-863.6mV  6.238mA    21.05mA    3.309mA
-818.2mV  3.071mA    14.07mA    2.668mA
-727.3mV  1.364mA    4.256mA    1.737mA
-681.8mV  1.02mA     2.019mA    1.336mA
-500mV    171uA      194.3uA    230.4uA
0V        214.9pA    5.588nA    92.86pA
[Pulldown]
|   voltage   I(typ)   I(min)   I(max)
-1.5V     -14.74mA   -12.19mA   -16.16mA
-1.227V   -15.31mA   -11.97mA   -17.6mA
-909.1mV  -16.6mA    -11.3mA    -21.18mA
-681.8mV  -16.35mA   -11.08mA   -19.67mA
-454.5mV  -11.91mA   -8.507mA   -14.74mA
272.7mV   6.362mA    3.997mA    8.501mA
545.5mV   10.24mA    5.995mA    14.59mA
772.7mV   11.69mA    6.665mA    17.39mA
1.227V    12.9mA     7.352mA    19.28mA
2.045V    13.75mA    7.656mA    20.64mA
2.5V      12.79mA    7.744mA    19.78mA
3V        13.46mA    8.49mA     18.71mA
[GND_clamp]
|   voltage   I(typ)   I(min)   I(max)
-1.5V     -195.5mA   -194.1mA   -199.3mA
-1.227V   -113.8mA   -124.5mA   -107mA
-1.045V   -61.55mA   -79.59mA   -48.43mA
-954.5mV  -37.21mA   -58.07mA   -22.7mA
-893.9mV  -22.74mA   -44.36mA   -10.65mA
-863.6mV  -16.14mA   -37.69mA   -6.624mA
-803mV    -6.914mA   -25.34mA   -4.002mA
-772.7mV  -3.892mA   -19.56mA   -3.316mA
-712.1mV  -1.754mA   -10.17mA   -2.298mA
-651.5mV  -919.5uA   -3.984mA   -1.444mA
-590.9mV  -443.7uA   -1.105mA   -766.2uA
1.5V      214.9pA    164.2nA    51.74pA
[Ramp]
| variable   typ   min   max
dV/dt_f   0.3882/0.26194252u   0.227112/0.38271138u   0.559158/0.19429291u
dV/dt_r 31.802776m/0.13405768n 18.621748m/0.16729346n 46.553623m/0.11856545n
R_load = 50
[Rising Waveform]
R_fixture = 1000
V_fixture = 1.5
V_fixture_min = 1.35
V_fixture_max = 1.65
|   time   V(typ)   V(min)   V(max)
0s        54.45mV    73.03mV    46.5mV
983.3ps   125.8mV    88.19mV    20.95mV
1.292ns   141.7mV    152.3mV    40.92mV
1.69ns    171.5mV    249.6mV    113.5mV
3.36ns    400.6mV    410.5mV    446.4mV
6.906ns   736.3mV    668.2mV    786.9mV
15.18ns   1.151V     1.045V     1.236V
26.8ns    1.393V     1.26V      1.515V
44.58ns   1.485V     1.337V     1.63V
1.25us    1.5V       1.35V      1.65V
[Rising Waveform]
R_fixture = 50
V_fixture = 1.5
V_fixture_min = 1.35
V_fixture_max = 1.65
|   time   V(typ)   V(min)   V(max)
0s        893.7mV    997mV      778.5mV
376.4ps   911.9mV    999.4mV    834.5mV
560.9ps   966.4mV    1.006V     1.123V
732.8ps   1.141V     1.018V     1.405V
1.073ns   1.383V     1.105V     1.494V
1.471ns   1.405V     1.279V     1.504V
2.004ns   1.413V     1.3V       1.518V
7.638ns   1.479V     1.323V     1.635V
19.64ns   1.5V       1.349V     1.65V
1.25us    1.5V       1.35V      1.65V
[Falling Waveform]
R_fixture = 1000
V_fixture = 1.5
V_fixture_min = 1.35
V_fixture_max = 1.65
|   time   V(typ)   V(min)   V(max)
0s        1.5V       1.35V      1.65V
299.7ps   1.5V       1.35V      1.65V
744.4ps   1.673V     1.384V     1.938V
1.364ns   1.789V     1.505V     1.88V
40.71ns   1.51V      1.356V     1.65V
205.5ns   1.179V     1.241V     965.9mV
305.4ns   858.1mV    1.096V     69.57mV
439.9ns   81.56mV    844mV      46.67mV
669ns     53.99mV    120.8mV    46.5mV
1.25us    53.9mV     73.03mV    46.5mV
[Falling Waveform]
R_fixture = 50
V_fixture = 1.5
V_fixture_min = 1.35
V_fixture_max = 1.65
|   time   V(typ)   V(min)   V(max)
0s        1.5V       1.35V      1.65V
879.9ps   1.54V      1.373V     1.71V
11.19ns   1.499V     1.349V     1.649V
133.6ns   1.416V     1.326V     1.448V
223.3ns   1.308V     1.286V     1.227V
307.1ns   1.183V     1.24V      924.1mV
377.1ns   1.057V     1.197V     816.6mV
464.8ns   953.7mV    1.14V      784.5mV
577.9ns   907.6mV    1.073V     778.4mV
1.25us    893.7mV    997mV      777.8mV
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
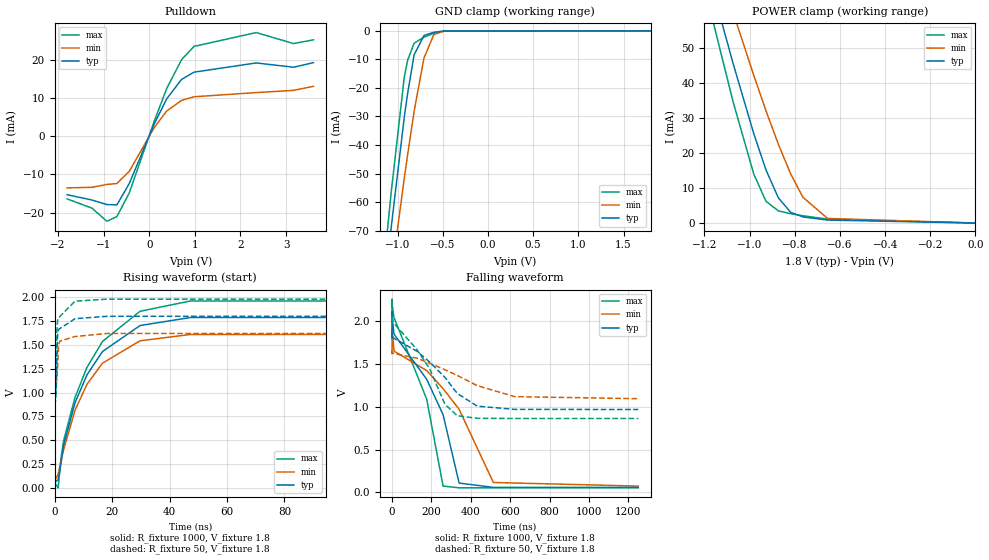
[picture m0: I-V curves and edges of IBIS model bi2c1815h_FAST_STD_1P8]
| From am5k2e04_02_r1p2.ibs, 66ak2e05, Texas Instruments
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|   Model Cell bi2c1815h_FAST_STD_1P8
|bi2c1815h_FAST_STD_1P8
[Model]   bi2c1815h_FAST_STD_1P8
Model_type   I/O_open_drain
Polarity   Non-Inverting
Enable   Active-Low
Vinl =  0.54
Vinh =  1.26
Cref =  15.0000pF
Rref =  100.0000M
Vref =  1.8
Vmeas =  0.9
C_comp   7.82904p   2.84791p   8.43627p
[Model Spec]
Vinl   0.54   0.486   0.594
Vinh   1.26   1.134   1.386
[Temperature Range]   25   125   -40
[Voltage Range]   1.8   1.62   1.98
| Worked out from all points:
|   slope of the pulldown table from 0 to 0.27 V, typ, clamps not added: 37.1 ohm
|   GND clamp passes 1 mA (typ) near -0.66 V on its own axis
|   POWER clamp passes 1 mA (typ) near -0.68 V on its own axis
|   rising waveform, R_fixture 1000, V_fixture 1.8: 20-80 % time 14.3ns typ, 13.7ns min, 15.5ns max; typ from 0.059 V to 1.8 V
|   rising waveform, R_fixture 50, V_fixture 1.8: 20-80 % time 416ps typ, 512ps min, 416ps max; typ from 0.966 V to 1.8 V
|   falling waveform, R_fixture 1000, V_fixture 1.8: 20-80 % time 164ns typ, 231ns min, 129ns max; typ from 1.8 V to 0.059 V
|   falling waveform, R_fixture 50, V_fixture 1.8: 20-80 % time 207ns typ, 294ns min, 157ns max; typ from 1.8 V to 0.966 V
| Nom Voltages:
|   VDD=0.95, VDDS=1.8, ESD_BIASFET=0, VSS=0, VSSS=0
| Min Voltages:
|   VDD=0.81, VDDS=1.62, ESD_BIASFET=0, VSS=0, VSSS=0
| Max Voltages:
|   VDD=0.998, VDDS=1.98, ESD_BIASFET=0, VSS=0, VSSS=0
[POWER_clamp]
|   voltage   I(typ)   I(min)   I(max)
-1.8V     228.3mA    217.1mA    239.9mA
-1.182V   71.41mA    82.7mA     63.22mA
-1.164V   67.02mA    78.9mA     58.31mA
-1.127V   58.34mA    71.38mA    48.65mA
-1.073V   45.63mA    60.27mA    34.69mA
-981.8mV  25.64mA    42.31mA    14.07mA
-927.3mV  15.19mA    32.09mA    6.201mA
-872.7mV  7.212mA    22.55mA    3.494mA
-818.2mV  3.071mA    14.07mA    2.668mA
-763.6mV  1.749mA    7.355mA    2.087mA
-654.5mV  846uA      1.319mA    1.117mA
0V        320.1pA    6.203nA    1.2nA
[Pulldown]
|   voltage   I(typ)   I(min)   I(max)
-1.8V     -15.34mA   -13.56mA   -16.43mA
-1.255V   -16.73mA   -13.4mA    -18.86mA
-927.3mV  -17.92mA   -12.65mA   -22.3mA
-709.1mV  -18.01mA   -12.41mA   -21.06mA
-436.4mV  -12.4mA    -9.209mA   -14.87mA
109.1mV   3.162mA    2.233mA    3.875mA
381.8mV   9.743mA    6.546mA    12.41mA
709.1mV   14.85mA    9.354mA    20.03mA
981.8mV   16.74mA    10.3mA     23.49mA
2.345V    19.16mA    11.4mA     27.11mA
3.164V    18.03mA    11.98mA    24.23mA
3.6V      19.24mA    13.03mA    25.22mA
[GND_clamp]
|   voltage   I(typ)   I(min)   I(max)
-1.8V     -287mA     -272.2mA   -302.8mA
-1.182V   -100.5mA   -113.1mA   -91.98mA
-1.145V   -89.92mA   -104mA     -80.05mA
-1.109V   -79.52mA   -95.11mA   -68.4mA
-1.073V   -69.22mA   -86.23mA   -56.94mA
-927.3mV  -30.39mA   -51.8mA    -16.31mA
-890.9mV  -22.12mA   -43.71mA   -10.41mA
-818.2mV  -8.424mA   -28.23mA   -4.346mA
-709.1mV  -1.635mA   -9.541mA   -2.241mA
-600mV    -499.1uA   -1.337mA   -852.9uA
-490.9mV  -80.16uA   -133.6uA   -148.6uA
1.8V      320.1pA    340nA      252.2pA
[Ramp]
| variable   typ   min   max
dV/dt_f   0.534648/0.22652212u   0.33942/0.31961145u   0.718608/0.17384655u
dV/dt_r 43.878902m/0.1341492n 27.847838m/0.15616846n 60.369256m/0.1408838n
R_load = 50
[Rising Waveform]
R_fixture = 1000
V_fixture = 1.8
V_fixture_min = 1.62
V_fixture_max = 1.98
|   time   V(typ)   V(min)   V(max)
0s        58.68mV    73.88mV    53.2mV
1.171ns   84.61mV    141.6mV    0V
2.239ns   271.1mV    293.5mV    322.8mV
3.075ns   445.3mV    398.4mV    493.9mV
7.046ns   892.1mV    814.3mV    948.9mV
11.23ns   1.186V     1.087V     1.265V
16.61ns   1.43V      1.308V     1.536V
29.72ns   1.703V     1.543V     1.853V
47.21ns   1.787V     1.609V     1.96V
1.25us    1.8V       1.62V      1.98V
[Rising Waveform]
R_fixture = 50
V_fixture = 1.8
V_fixture_min = 1.62
V_fixture_max = 1.98
|   time   V(typ)   V(min)   V(max)
0s        966.2mV    1.092V     862.1mV
378.4ps   992.8mV    1.097V     932.3mV
527.1ps   1.059V     1.106V     1.229V
706.5ps   1.325V     1.128V     1.657V
1.034ns   1.64V      1.311V     1.772V
1.356ns   1.662V     1.503V     1.782V
1.783ns   1.671V     1.54V      1.798V
7.071ns   1.775V     1.588V     1.959V
18.39ns   1.8V       1.62V      1.98V
1.25us    1.8V       1.62V      1.98V
[Falling Waveform]
R_fixture = 1000
V_fixture = 1.8
V_fixture_min = 1.62
V_fixture_max = 1.98
|   time   V(typ)   V(min)   V(max)
0s        1.8V       1.62V      1.98V
421.2ps   1.939V     1.621V     2.252V
936.7ps   2.106V     1.785V     2.23V
1.698ns   2.023V     1.897V     2.181V
10.55ns   1.844V     1.647V     2.037V
176.6ns   1.317V     1.419V     1.085V
259.6ns   906.2mV    1.21V      74.07mV
340.9ns   108.9mV    968.2mV    53.67mV
514.6ns   58.87mV    115.8mV    53.21mV
1.25us    58.68mV    73.89mV    53.2mV
[Falling Waveform]
R_fixture = 50
V_fixture = 1.8
V_fixture_min = 1.62
V_fixture_max = 1.98
|   time   V(typ)   V(min)   V(max)
0s        1.8V       1.62V      1.98V
567.2ps   1.856V     1.645V     2.059V
6.496ns   1.8V       1.619V     1.98V
125.2ns   1.648V     1.565V     1.669V
191.1ns   1.519V     1.506V     1.442V
268.7ns   1.341V     1.43V      1.028V
331.3ns   1.154V     1.363V     894.1mV
432.9ns   1.005V     1.244V     863.4mV
622.6ns   967.7mV    1.116V     861.3mV
1.25us    966.2mV    1.092V     861.3mV
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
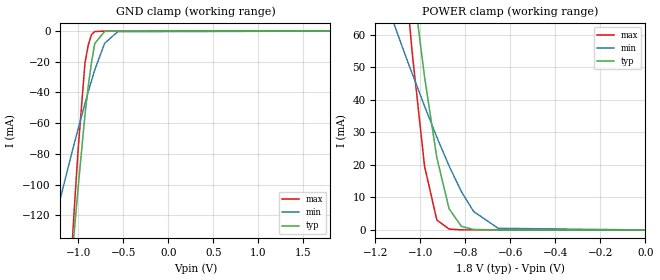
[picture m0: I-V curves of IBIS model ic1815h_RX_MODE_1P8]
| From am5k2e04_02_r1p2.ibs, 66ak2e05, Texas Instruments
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|   Model Cell ic1815h_RX_MODE_1P8
|RX_MODE_1P8
[Model]   ic1815h_RX_MODE_1P8
Model_type   Input
Polarity   Non-Inverting
Vinl =  0.63
Vinh =  1.17
C_comp   0.751145p   0.686962p   0.76914p
[Model Spec]
Vinl   0.63   0.567   0.693
Vinh   1.17   1.053   1.287
[Temperature Range]   25   125   -40
[Voltage Range]   1.8   1.62   1.98
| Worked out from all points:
|   GND clamp passes 1 mA (typ) near -0.74 V on its own axis
|   POWER clamp passes 1 mA (typ) near -0.81 V on its own axis
[POWER_clamp]
|   voltage   I(typ)   I(min)   I(max)
-1.8V     581.8mA    200.6mA    780.9mA
-1.182V   165.8mA    75.68mA    178.2mA
-1.073V   98.17mA    54.79mA    83mA
-1.055V   87.42mA    51.38mA    68.49mA
-1.036V   76.67mA    47.97mA    53.99mA
-981.8mV  47.03mA    38.05mA    19.56mA
-927.3mV  22.23mA    28.53mA    3.063mA
-872.7mV  6.505mA    19.66mA    276.7uA
-818.2mV  1.11mA     11.8mA     40.92uA
-763.6mV  159uA      5.662mA    20.48uA
-654.5mV  10.03uA    510.5uA    11.78uA
0V        47.26pA    161.3pA    66.24pA
[GND_clamp]
|   voltage   I(typ)   I(min)   I(max)
-1.8V     -691.6mA   -252.4mA   -924.6mA
-1.291V   -306.2mA   -129.9mA   -367.2mA
-1.073V   -148.8mA   -79.28mA   -141.6mA
-1.036V   -123.7mA   -71.04mA   -106.4mA
-1V       -99.71mA   -62.98mA   -74.44mA
-927.3mV  -54.49mA   -47.17mA   -20.77mA
-890.9mV  -35.78mA   -39.62mA   -9.067mA
-854.5mV  -20.32mA   -32.3mA    -2.241mA
-818.2mV  -8.105mA   -25.21mA   -290.4uA
-709.1mV  -211.7uA   -7.969mA   -11uA
-563.6mV  -2.721uA   -418uA     -2.323uA
1.8V      47.26pA    5.374nA    45.33pA
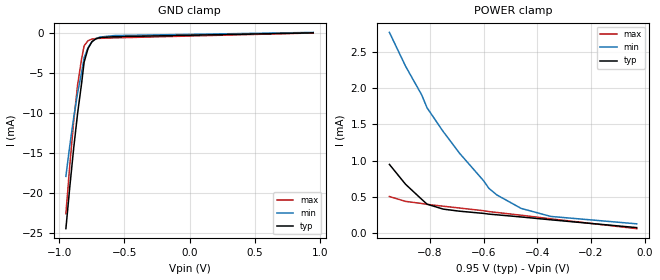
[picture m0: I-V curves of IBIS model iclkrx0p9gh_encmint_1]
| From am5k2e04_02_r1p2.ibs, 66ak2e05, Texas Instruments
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|   Model Cell iclkrx0p9gh_encmint_1
|iclkrx0p9gh_encmint_1.ibs   [10Feb12 revision 1.0]
|iclkrx0p9gh_encmint_1
[Model]   iclkrx0p9gh_encmint_1
Model_type   Input
Polarity   Non-Inverting
Vinl =  1.15
Vinh =  1.25
C_comp   1p   1p   1p
[Model Spec]
Vinl   1.15   1.15   1.15
Vinh   1.25   1.25   1.25
[Temperature Range]   25   125   -40
[Voltage Range]   0.95   0.81   0.998
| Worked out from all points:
|   GND clamp passes 1 mA (typ) near -0.75 V on its own axis
[GND_clamp]
|   voltage   I(typ)   I(min)   I(max)
-950mV    -24.43mA   -17.89mA   -22.56mA
-920mV    -19.2mA    -14.04mA   -16.48mA
-890mV    -14.35mA   -10.53mA   -11mA
-860mV    -9.997mA   -7.452mA   -6.449mA
-830mV    -6.338mA   -4.926mA   -3.25mA
-810mV    -3.602mA   -3.039mA   -1.564mA
-780mV    -1.9mA     -1.79mA    -920.3uA
-750mV    -1.047mA   -1.06mA    -715.9uA
-720mV    -683.1uA   -670.7uA   -651.2uA
-690mV    -537.6uA   -473.5uA   -625.5uA
-580mV    -424.3uA   -279.1uA   -571.6uA
950mV     63.95uA    117.8uA    47.04uA
[POWER_clamp]
|   voltage   I(typ)   I(min)   I(max)
-950mV    946.7uA    2.771mA    503.3uA
-890mV    672.6uA    2.304mA    435.8uA
-830mV    464.8uA    1.908mA    407.1uA
-810mV    397.7uA    1.729mA    394.4uA
-750mV    329.2uA    1.401mA    369.5uA
-690mV    300.8uA    1.105mA    344.7uA
-600mV    270.1uA    722.4uA    307.4uA
-580mV    260.3uA    616.2uA    294.9uA
-550mV    250.4uA    524.1uA    282.5uA
-460mV    220.9uA    339uA      245.1uA
-350mV    181.5uA    227.9uA    195.2uA
-30mV     73.62uA    125.8uA    59.12uA
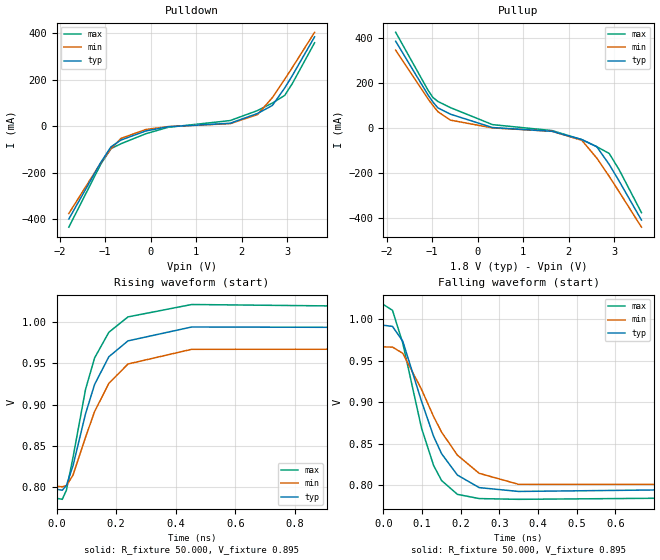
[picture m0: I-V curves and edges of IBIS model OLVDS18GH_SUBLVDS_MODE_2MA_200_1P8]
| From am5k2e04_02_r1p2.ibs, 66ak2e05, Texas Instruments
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[Model]   OLVDS18GH_SUBLVDS_MODE_2MA_200_1P8
Model_type   Output
Polarity   Non-Inverting
Cref =  15.0001pF
Rref =  101.0000M
Vref =  0V
Vmeas =  1.08V
C_comp   1p   1p   1p
[Temperature Range]   25   125   -40
[Voltage Range]   1.8   1.62   1.98
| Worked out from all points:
|   slope of the pulldown table from 0 to 0.27 V, typ, clamps not added: 26.8 ohm
|   slope of the pullup table from 0 to 0.27 V, typ, clamps not added: 21.6 ohm
|   rising waveform, R_fixture 50.000, V_fixture 0.895: 20-80 % time 106ps typ, 118ps min, 92.6ps max; typ from 0.797 V to 0.993 V
|   falling waveform, R_fixture 50.000, V_fixture 0.895: 20-80 % time 87ps typ, 114ps min, 73ps max; typ from 0.993 V to 0.797 V
| Nom Voltages:
[Pulldown]
|   voltage   I(typ)   I(min)   I(max)
-1.8V     -399.5mA   -375.8mA   -434.4mA
-1.091V   -153.9mA   -155.7mA   -161.1mA
-872.7mV  -88.78mA   -96.76mA   -96.49mA
-654.5mV  -59.73mA   -52.62mA   -75.55mA
-109.1mV  -20.65mA   -14.23mA   -32.54mA
381.8mV   -2.48mA    -1.863mA   -4.928mA
1.745V    12.62mA    10.84mA    24.1mA
2.345V    54.53mA    49.66mA    67.05mA
2.673V    89.19mA    122.9mA    99.41mA
2.945V    164.6mA    202.3mA    132.6mA
3.109V    217mA      251.7mA    182.6mA
3.6V      384.3mA    403.7mA    358.9mA
[Pullup]
|   voltage   I(typ)   I(min)   I(max)
-1.8V     385.1mA    345.5mA    425mA
-1.091V   146.6mA    129.2mA    167.8mA
-981.8mV  114.5mA    99.01mA    135mA
-872.7mV  88.74mA    71.91mA    117.2mA
-600mV    60.79mA    34.27mA    90.03mA
327.3mV   1.069mA    -573.4uA   14.1mA
1.636V    -15.64mA   -15.5mA    -12.35mA
2.291V    -52.63mA   -56.02mA   -52.58mA
2.618V    -84.29mA   -134.8mA   -84.08mA
2.891V    -163mA     -216.1mA   -114.2mA
3.109V    -237mA     -284.9mA   -186.5mA
3.6V      -410.8mA   -442.3mA   -377.6mA
[Ramp]
| variable   typ   min   max
dV/dt_f   7.476m/1.6544072n   2.562m/0.26059293n   3.144m/2.6225123n
dV/dt_r   4.176m/2.0540781n   1.428m/1.7467396n   3.372m/0.2199629n
R_load = 50
[Rising Waveform]
R_fixture = 50.000
V_fixture = 0.895
V_fixture_min = 0.882
V_fixture_max = 0.901
|  time   V(typ)   V(min)   V(max)
0s        797.4mV    801.1mV    786.6mV
19.2ps    796.3mV    800.5mV    785.3mV
33.1ps    802mV      801.8mV    796.3mV
55.3ps    826mV      814.6mV    836.1mV
97.3ps    888.8mV    860.4mV    918.3mV
127.7ps   924.3mV    891.5mV    956.4mV
175.5ps   957.8mV    925.6mV    987.4mV
239.7ps   977mV      949mV      1.006V
453.4ps   993.8mV    966.8mV    1.021V
1.262ns   993.1mV    966.9mV    1.018V
[Falling Waveform]
R_fixture = 50.000
V_fixture = 0.895
V_fixture_min = 0.882
V_fixture_max = 0.901
|  time   V(typ)   V(min)   V(max)
0s        993mV      966.9mV    1.018V
23.5ps    991.6mV    966.7mV    1.011V
50.1ps    973.8mV    959.2mV    971.4mV
98.5ps    901.6mV    915.9mV    869.3mV
130ps     859mV      882.9mV    823.9mV
150.6ps   838.2mV    864.2mV    805.9mV
191.5ps   812.5mV    836.5mV    789.3mV
247.9ps   797.4mV    814.6mV    784.2mV
349.7ps   792.8mV    801.4mV    783.3mV
1.262ns   797.4mV    801.1mV    786.6mV
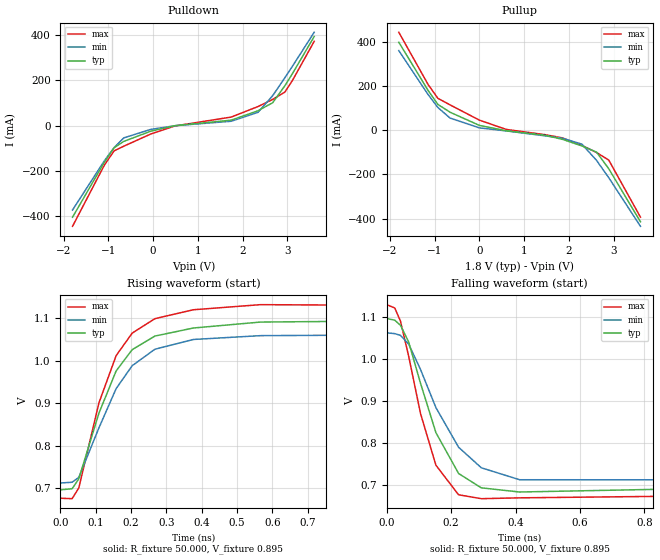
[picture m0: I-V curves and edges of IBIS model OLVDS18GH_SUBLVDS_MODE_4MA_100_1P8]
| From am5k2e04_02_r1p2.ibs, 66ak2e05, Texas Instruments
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|   Model Cell OLVDS18GH_SUBLVDS_MODE_4MA_100_1P8
|olvds18gh.ibs [30Dec11 revision 1.0]
|OLVDS18GH_SUBLVDS_MODE_4MA_100_1P8
[Model]   OLVDS18GH_SUBLVDS_MODE_4MA_100_1P8
Model_type   Output
Polarity   Non-Inverting
Cref =  15.0001pF
Rref =  101.0000M
Vref =  0V
Vmeas =  1.08V
C_comp   1p   1p   1p
[Temperature Range]   25   125   -40
[Voltage Range]   1.8   1.62   1.98
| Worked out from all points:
|   slope of the pulldown table from 0 to 0.27 V, typ, clamps not added: 18.6 ohm
|   slope of the pullup table from 0 to 0.27 V, typ, clamps not added: 14.4 ohm
|   rising waveform, R_fixture 50.000, V_fixture 0.895: 20-80 % time 118ps typ, 124ps min, 105ps max; typ from 0.696 V to 1.1 V
|   falling waveform, R_fixture 50.000, V_fixture 0.895: 20-80 % time 103ps typ, 135ps min, 83.9ps max; typ from 1.1 V to 0.696 V
| Nom Voltages:
[Pulldown]
|   voltage   I(typ)   I(min)   I(max)
-1.8V     -404.8mA   -372.9mA   -445mA
-1.091V   -162.6mA   -156mA     -175.4mA
-872.7mV  -98.04mA   -97.48mA   -111.7mA
-654.5mV  -69.69mA   -54.23mA   -90.84mA
-54.55mV  -24.71mA   -16.72mA   -37.34mA
490.9mV   -174.8uA   -398.3uA   -1.227mA
1.745V    24.13mA    19.34mA    37.76mA
2.345V    65.83mA    58.88mA    84.39mA
2.673V    101.3mA    132.6mA    115.8mA
2.945V    176.2mA    211.6mA    148.4mA
3.109V    228.2mA    261mA      197.9mA
3.6V      393.8mA    412.6mA    372.5mA
[Pullup]
|   voltage   I(typ)   I(min)   I(max)
-1.8V     397.5mA    359.4mA    442.4mA
-1.145V   179.3mA    160.8mA    206.2mA
-927.3mV  116.3mA    102.3mA    143.9mA
-654.5mV  80.82mA    54.33mA    114mA
0V        21.36mA    10.1mA     45.21mA
600mV     -3.053mA   -3.581mA   3.051mA
1.473V    -23.52mA   -26.15mA   -20.78mA
1.855V    -41.74mA   -36.73mA   -35.17mA
2.291V    -71.5mA    -63.4mA    -69.06mA
2.618V    -99.47mA   -136.7mA   -101.3mA
2.891V    -174.5mA   -215.1mA   -135.4mA
3.6V      -414.5mA   -435.1mA   -393.7mA
[Ramp]
| variable   typ   min   max
dV/dt_f   9.102m/0.42698704n   7.128m/0.8680283n   16.134m/2.2554648n
dV/dt_r   4.356m/0.7007268n   7.368m/3.1466935n   12.99m/4.1871362n
R_load = 50
[Rising Waveform]
R_fixture = 50.000
V_fixture = 0.895
V_fixture_min = 0.882
V_fixture_max = 0.901
|  time   V(typ)   V(min)   V(max)
0s        695.8mV    711.9mV    675.9mV
33ps      698.3mV    713.6mV    674.9mV
52ps      721.8mV    725.2mV    700.2mV
109ps     876.5mV    841.9mV    900.7mV
157.7ps   975.9mV    934.3mV    1.012V
203.1ps   1.026V     988.2mV    1.065V
267.4ps   1.058V     1.027V     1.099V
376.3ps   1.077V     1.05V      1.12V
566.3ps   1.091V     1.059V     1.132V
1.262ns   1.096V     1.062V     1.129V
[Falling Waveform]
R_fixture = 50.000
V_fixture = 0.895
V_fixture_min = 0.882
V_fixture_max = 0.901
|  time   V(typ)   V(min)   V(max)
0s        1.096V     1.062V     1.129V
25ps      1.092V     1.06V      1.121V
42.6ps    1.08V      1.056V     1.09V
68.2ps    1.04V      1.035V     1.006V
104.9ps   941.9mV    974.8mV    869.8mV
152.7ps   824.3mV    883.8mV    746.7mV
223.1ps   727mV      789.5mV    676.3mV
293.6ps   692.8mV    740.6mV    667mV
412.6ps   682.9mV    712.1mV    669mV
1.262ns   695.6mV    711.9mV    676mV
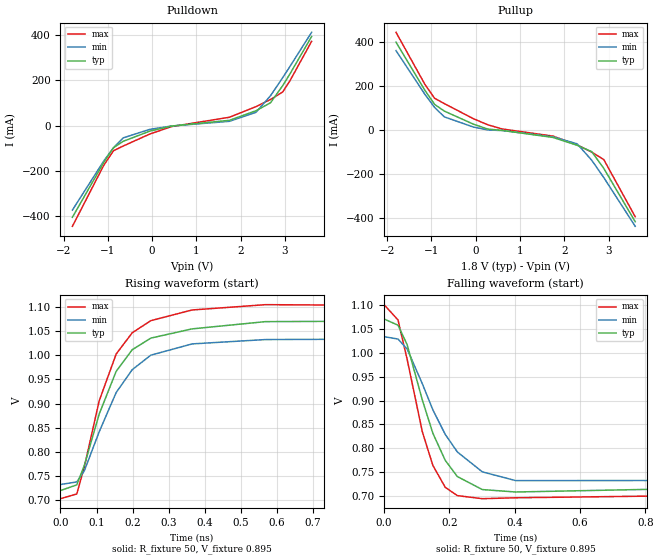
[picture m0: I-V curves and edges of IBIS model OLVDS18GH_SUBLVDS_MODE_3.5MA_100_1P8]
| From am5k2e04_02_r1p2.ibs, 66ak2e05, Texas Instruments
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[Model]   OLVDS18GH_SUBLVDS_MODE_3.5MA_100_1P8
Model_type   Output
Polarity   Non-Inverting
Cref =  15.0001pF
Rref =  101.0000M
Vref =  0V
Vmeas =  1.08V
C_comp   1p   1p   1p
[Temperature Range]   25   125   -40
[Voltage Range]   1.8   1.62   1.98
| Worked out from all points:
|   slope of the pulldown table from 0 to 0.27 V, typ, clamps not added: 19.3 ohm
|   slope of the pullup table from 0 to 0.27 V, typ, clamps not added: 15 ohm
|   rising waveform, R_fixture 50, V_fixture 0.895: 20-80 % time 113ps typ, 120ps min, 101ps max; typ from 0.72 V to 1.07 V
|   falling waveform, R_fixture 50, V_fixture 0.895: 20-80 % time 96.7ps typ, 129ps min, 79.5ps max; typ from 1.07 V to 0.72 V
| Nom Voltages:
[Pulldown]
|   voltage   I(typ)   I(min)   I(max)
-1.8V     -405.8mA   -373.8mA   -445.8mA
-1.091V   -162.8mA   -156.5mA   -175.3mA
-872.7mV  -98.21mA   -97.86mA   -111.5mA
-654.5mV  -69.78mA   -54.55mA   -90.68mA
-54.55mV  -24.81mA   -16.91mA   -37.67mA
436.4mV   -2.345mA   -2.086mA   -4.615mA
1.745V    23.21mA    18.76mA    36.73mA
2.345V    65.66mA    58.53mA    83.7mA
2.673V    101mA      132.3mA    115.4mA
2.945V    176mA      211.5mA    148.2mA
3.109V    228mA      260.9mA    197.7mA
3.6V      393.9mA    412.7mA    372.6mA
[Pullup]
|   voltage   I(typ)   I(min)   I(max)
-1.8V     397.1mA    359mA      441.9mA
-1.145V   178.3mA    160.1mA    205.1mA
-927.3mV  115.3mA    101.4mA    143mA
-709.1mV  85.07mA    58.9mA     119mA
-54.55mV  26.04mA    12.96mA    50.83mA
272.7mV   3.476mA    -361.6uA   22.97mA
600mV     -2.241mA   -3.043mA   4.011mA
1.745V    -34.34mA   -31.46mA   -28.21mA
2.291V    -69.79mA   -63.39mA   -68.21mA
2.618V    -98.57mA   -137.3mA   -100.6mA
2.891V    -174.3mA   -216mA     -134.5mA
3.6V      -415.8mA   -436.6mA   -393.3mA
[Ramp]
| variable   typ   min   max
dV/dt_f   9.168m/0.54580181n   6.258m/0.87542358n   13.554m/2.6105065n
dV/dt_r   4.566m/0.76482702n   6.708m/3.2743951n   3.168m/0.10664755n
R_load = 50
[Rising Waveform]
R_fixture = 50
V_fixture = 0.895
V_fixture_min = 0.8825
V_fixture_max = 0.90115
|   time   V(typ)   V(min)   V(max)
0s        720.4mV    732.8mV    703.6mV
45.3ps    732.1mV    738.2mV    713.3mV
66.3ps    772.3mV    761.2mV    769.6mV
107.5ps   878.4mV    841.8mV    905.6mV
154.5ps   966.3mV    922.6mV    1.002V
199ps     1.011V     969.8mV    1.046V
250.7ps   1.035V     999.8mV    1.071V
364.9ps   1.054V     1.023V     1.093V
568.8ps   1.069V     1.032V     1.104V
1.262ns   1.071V     1.034V     1.101V
[Falling Waveform]
R_fixture = 50
V_fixture = 0.895
V_fixture_min = 0.8825
V_fixture_max = 0.90115
|   time   V(typ)   V(min)   V(max)
0s        1.071V     1.034V     1.101V
42.8ps    1.058V     1.029V     1.069V
70.9ps    1.017V     1.008V     986.2mV
117.3ps   901.3mV    935.3mV    834.7mV
149.7ps   831.4mV    880.5mV    764.1mV
187.5ps   774.9mV    829.2mV    718.4mV
224.7ps   740.9mV    792.4mV    701mV
301ps     713.7mV    750.8mV    694.6mV
403ps     708.6mV    732.5mV    696.5mV
1.262ns   720.3mV    732.8mV    703.8mV
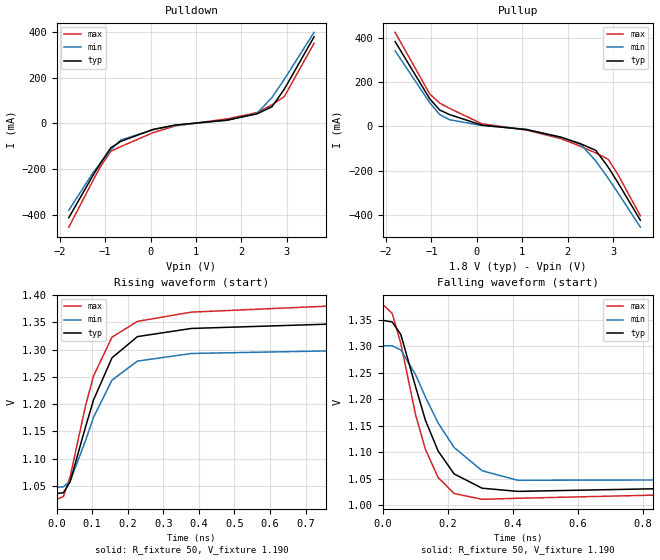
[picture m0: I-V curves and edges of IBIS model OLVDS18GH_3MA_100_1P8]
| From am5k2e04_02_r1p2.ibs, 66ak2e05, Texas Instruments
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|   Model Cell OLVDS18GH_3MA_100_1P8
|olvds18gh.ibs [30Dec11 revision 1.0]
|OLVDS18GH_3MA_100_1P8
[Model]   OLVDS18GH_3MA_100_1P8
Model_type   Output
Polarity   Non-Inverting
Cref =  15.0001pF
Rref =  101.0000M
Vref =  0V
Vmeas =  1.08V
C_comp   1p   1p   1p
[Temperature Range]   25   125   -40
[Voltage Range]   1.8   1.62   1.98
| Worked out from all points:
|   slope of the pulldown table from 0 to 0.27 V, typ, clamps not added: 18.7 ohm
|   slope of the pullup table from 0 to 0.27 V, typ, clamps not added: 26.3 ohm
|   rising waveform, R_fixture 50, V_fixture 1.190: 20-80 % time 98.8ps typ, 99ps min, 92.6ps max; typ from 1.04 V to 1.35 V
|   falling waveform, R_fixture 50, V_fixture 1.190: 20-80 % time 98.7ps typ, 137ps min, 82.2ps max; typ from 1.35 V to 1.04 V
| Nom Voltages:
[Pulldown]
|   voltage   I(typ)   I(min)   I(max)
-1.8V     -412.7mA   -380.4mA   -454.2mA
-1.255V   -223.5mA   -211.8mA   -245.5mA
-1.091V   -170.4mA   -172.8mA   -185.2mA
-872.7mV  -106.4mA   -115.2mA   -122.1mA
-654.5mV  -78.57mA   -72.55mA   -101.5mA
54.55mV   -26.25mA   -28.26mA   -40.93mA
545.5mV   -7.095mA   -8.15mA    -10.74mA
1.691V    14.79mA    13.32mA    19.95mA
2.345V    41.86mA    44.31mA    47.42mA
2.673V    72.77mA    113mA      81.25mA
2.945V    149.7mA    192.9mA    117.1mA
3.6V      378.9mA    398.7mA    350.7mA
[Pullup]
|   voltage   I(typ)   I(min)   I(max)
-1.8V     383.3mA    341.3mA    424.9mA
-1.036V   123.9mA    106.3mA    145.6mA
-818.2mV  73.71mA    53.1mA     105mA
-600mV    52.85mA    29.75mA    81.2mA
109.1mV   5.404mA    3.618mA    11.46mA
1.091V    -15.08mA   -13.25mA   -16.73mA
1.855V    -49.1mA    -50.35mA   -56.1mA
2.291V    -79.39mA   -81.88mA   -91.11mA
2.618V    -108.8mA   -156.7mA   -120.5mA
2.891V    -184.2mA   -234.5mA   -149mA
3.109V    -255.6mA   -301.3mA   -218.9mA
3.6V      -424.7mA   -455.9mA   -404.4mA
[Ramp]
| variable   typ   min   max
dV/dt_f   11.316m/1.115028n   4.878m/0.87536981n   5.286m/0.61121375n
dV/dt_r   5.616m/0.88179723n   5.154m/3.4136838n   4.872m/0.57290105n
R_load = 50
[Rising Waveform]
R_fixture = 50
V_fixture = 1.190
V_fixture_min = 1.1743
V_fixture_max = 1.20176
|   time   V(typ)   V(min)   V(max)
0s        1.036V     1.047V     1.025V
19.2ps    1.037V     1.048V     1.03V
38.1ps    1.057V     1.058V     1.066V
81.5ps    1.158V     1.133V     1.197V
104.2ps   1.208V     1.176V     1.252V
155.9ps   1.285V     1.244V     1.323V
227.4ps   1.324V     1.279V     1.352V
379.1ps   1.339V     1.293V     1.369V
866.2ps   1.349V     1.299V     1.383V
4.925ns   1.348V     1.3V       1.379V
[Falling Waveform]
R_fixture = 50
V_fixture = 1.190
V_fixture_min = 1.1743
V_fixture_max = 1.20176
|   time   V(typ)   V(min)   V(max)
0s        1.349V     1.301V     1.379V
28.9ps    1.346V     1.301V     1.362V
55.5ps    1.322V     1.293V     1.305V
101ps     1.223V     1.246V     1.17V
131.1ps   1.16V      1.204V     1.105V
170.2ps   1.102V     1.155V     1.052V
219.1ps   1.059V     1.109V     1.022V
305.2ps   1.032V     1.065V     1.011V
414.7ps   1.026V     1.047V     1.013V
1.262ns   1.036V     1.048V     1.025V
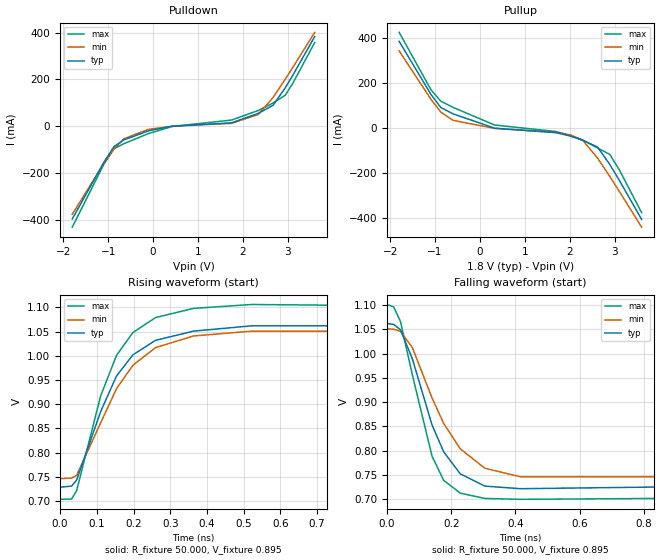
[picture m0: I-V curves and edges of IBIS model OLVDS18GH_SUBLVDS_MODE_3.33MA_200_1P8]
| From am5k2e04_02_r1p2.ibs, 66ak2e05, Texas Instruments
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|   Model Cell OLVDS18GH_SUBLVDS_MODE_3.33MA_200_1P8
|olvds18gh.ibs [30Dec11 revision 1.0]
|OLVDS18GH_SUBLVDS_MODE_3.33MA_200_1P8
[Model]   OLVDS18GH_SUBLVDS_MODE_3.33MA_200_1P8
Model_type   Output
Polarity   Non-Inverting
Cref =  15.0001pF
Rref =  101.0000M
Vref =  0V
Vmeas =  1.08V
C_comp   1p   1p   1p
[Temperature Range]   25   125   -40
[Voltage Range]   1.8   1.62   1.98
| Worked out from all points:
|   slope of the pulldown table from 0 to 0.27 V, typ, clamps not added: 24.2 ohm
|   slope of the pullup table from 0 to 0.27 V, typ, clamps not added: 18.6 ohm
|   rising waveform, R_fixture 50.000, V_fixture 0.895: 20-80 % time 117ps typ, 128ps min, 104ps max; typ from 0.729 V to 1.06 V
|   falling waveform, R_fixture 50.000, V_fixture 0.895: 20-80 % time 103ps typ, 131ps min, 85.2ps max; typ from 1.06 V to 0.729 V
[Pulldown]
|   voltage   I(typ)   I(min)   I(max)
-1.8V     -397.3mA   -377.5mA   -432.6mA
-1.091V   -153mA     -157.9mA   -160.9mA
-872.7mV  -88.04mA   -98.85mA   -96.42mA
-654.5mV  -59.23mA   -54.32mA   -75.63mA
-109.1mV  -20.47mA   -13.78mA   -32.07mA
436.4mV   140.4uA    -162.1uA   -1.032mA
1.745V    14.17mA    11.99mA    26.11mA
2.345V    54.89mA    50.51mA    67.23mA
2.673V    89.72mA    123mA      99.42mA
2.945V    164.9mA    201.7mA    132.8mA
3.109V    217.2mA    250.9mA    182.7mA
3.6V      384mA      401.9mA    358.3mA
[Pullup]
|   voltage   I(typ)   I(min)   I(max)
-1.8V     385.6mA    343mA      425.7mA
-1.091V   148.4mA    127.2mA    169.5mA
-872.7mV  90.61mA    70.27mA    118.7mA
-600mV    62.34mA    33.39mA    91.06mA
327.3mV   -1.573mA   -2.615mA   12.53mA
1.691V    -21.5mA    -20.35mA   -16.51mA
2.018V    -36.96mA   -31.67mA   -34.41mA
2.291V    -55.86mA   -55.87mA   -54.51mA
2.618V    -85.8mA    -134.9mA   -89.7mA
2.891V    -163.1mA   -216.4mA   -118.4mA
3.109V    -236.1mA   -285.2mA   -189.4mA
3.6V      -408.2mA   -442.7mA   -378mA
[Ramp]
| variable   typ   min   max
dV/dt_f   9.468m/1.1390995n   4.116m/0.92053274n   9.09m/3.1173286n
dV/dt_r   4.614m/1.1993727n   4.17m/3.4831115n   11.664m/4.1914777n
R_load = 50
[Rising Waveform]
R_fixture = 50.000
V_fixture = 0.895
V_fixture_min = 0.882
V_fixture_max = 0.901
|  time   V(typ)   V(min)   V(max)
0s        728.8mV    746.4mV    703.7mV
31.1ps    731mV      747.5mV    704.2mV
44.8ps    743.4mV    753.2mV    721.3mV
110.2ps   884.7mV    861.5mV    917mV
153.5ps   958.4mV    932.2mV    1.001V
198.1ps   1.002V     980.5mV    1.048V
259.8ps   1.032V     1.017V     1.079V
363.2ps   1.051V     1.041V     1.098V
521.7ps   1.062V     1.051V     1.106V
1.262ns   1.062V     1.051V     1.101V
[Falling Waveform]
R_fixture = 50.000
V_fixture = 0.895
V_fixture_min = 0.882
V_fixture_max = 0.901
|  time   V(typ)   V(min)   V(max)
0s        1.062V     1.051V     1.101V
20.9ps    1.06V      1.05V      1.096V
41.9ps    1.049V     1.046V     1.066V
79.1ps    988.9mV    1.012V     955.6mV
140.4ps   852.9mV    908.6mV    788.7mV
176.7ps   797.7mV    856.1mV    739mV
228.4ps   752.5mV    803.9mV    712.8mV
305ps     727.3mV    764mV      701.9mV
415.7ps   722mV      746.5mV    700.1mV
1.262ns   728.8mV    746.4mV    703.7mV
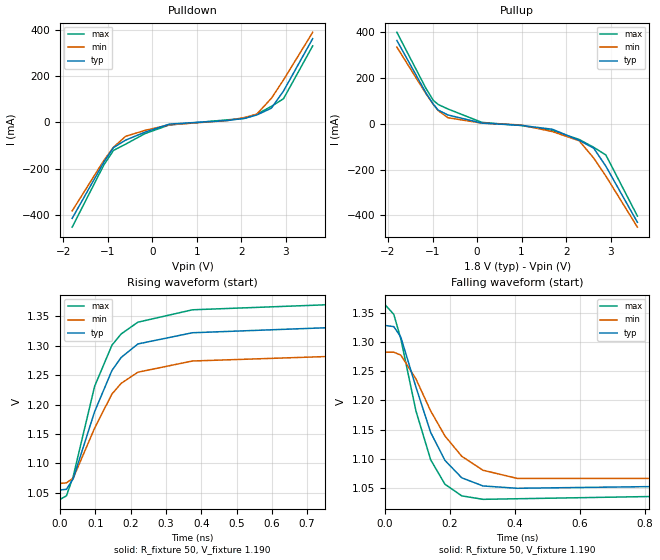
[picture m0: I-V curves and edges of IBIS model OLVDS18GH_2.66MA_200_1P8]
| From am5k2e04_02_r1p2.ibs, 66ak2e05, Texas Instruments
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[Model]   OLVDS18GH_2.66MA_200_1P8
Model_type   Output
Polarity   Non-Inverting
Cref =  15.0001pF
Rref =  101.0000M
Vref =  0V
Vmeas =  1.08V
C_comp   1p   1p   1p
[Temperature Range]   25   125   -40
[Voltage Range]   1.8   1.62   1.98
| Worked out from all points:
|   slope of the pulldown table from 0 to 0.27 V, typ, clamps not added: 14.1 ohm
|   slope of the pullup table from 0 to 0.27 V, typ, clamps not added: 40.9 ohm
|   rising waveform, R_fixture 50, V_fixture 1.190: 20-80 % time 108ps typ, 115ps min, 98.8ps max; typ from 1.05 V to 1.33 V
|   falling waveform, R_fixture 50, V_fixture 1.190: 20-80 % time 99.6ps typ, 133ps min, 85.7ps max; typ from 1.33 V to 1.05 V
[Pulldown]
|   voltage   I(typ)   I(min)   I(max)
-1.8V     -416.2mA   -383.8mA   -454.4mA
-1.091V   -173.3mA   -165.5mA   -185.2mA
-872.7mV  -109mA     -107.6mA   -121.2mA
-600mV    -76.6mA    -60.14mA   -94.26mA
-163.6mV  -41.99mA   -34.29mA   -48.13mA
381.8mV   -6.971mA   -10.21mA   -10.74mA
1.691V    8.53mA     8.392mA    11.51mA
2.073V    17.93mA    21.56mA    18mA
2.345V    32.47mA    36.27mA    35.33mA
2.673V    62.03mA    105mA      70.02mA
2.945V    136.6mA    184.8mA    103.1mA
3.6V      363.8mA    391.2mA    332.3mA
[Pullup]
|   voltage   I(typ)   I(min)   I(max)
-1.8V     362mA      333.1mA    397.7mA
-1.145V   133mA      129.5mA    152.4mA
-981.8mV  84.28mA    83.64mA    101.1mA
-872.7mV  58.78mA    56.72mA    83.34mA
-654.5mV  37.6mA     25.62mA    63.7mA
109.1mV   2.267mA    2.028mA    5.331mA
981.8mV   -7.686mA   -5.872mA   -8.048mA
1.691V    -24.5mA    -34.67mA   -30.11mA
2.291V    -72.87mA   -74.61mA   -69mA
2.618V    -106.8mA   -150mA     -103.1mA
2.891V    -185.4mA   -228.3mA   -136.6mA
3.6V      -430mA     -451.1mA   -402.8mA
[Ramp]
| variable   typ   min   max
dV/dt_f   10.068m/1.5071649n   2.37m/0.20918346n   5.01m/0.73730087n
dV/dt_r   5.16m/1.7134451n   1.71m/0.9824499n   4.452m/0.70271407n
R_load = 50
[Rising Waveform]
R_fixture = 50
V_fixture = 1.190
V_fixture_min = 1.1743
V_fixture_max = 1.20176
|   time   V(typ)   V(min)   V(max)
0s        1.055V     1.066V     1.039V
17.9ps    1.056V     1.067V     1.045V
37ps      1.074V     1.075V     1.078V
97.7ps    1.188V     1.16V      1.231V
146.9ps   1.258V     1.218V     1.301V
172.9ps   1.28V      1.236V     1.32V
220.5ps   1.303V     1.255V     1.34V
375ps     1.322V     1.274V     1.361V
775.6ps   1.331V     1.282V     1.37V
4.918ns   1.329V     1.282V     1.366V
[Falling Waveform]
R_fixture = 50
V_fixture = 1.190
V_fixture_min = 1.1743
V_fixture_max = 1.20176
|   time   V(typ)   V(min)   V(max)
0s        1.329V     1.283V     1.365V
27.5ps    1.327V     1.283V     1.348V
49ps      1.309V     1.278V     1.306V
95.6ps    1.223V     1.237V     1.182V
140.9ps   1.145V     1.182V     1.098V
184.8ps   1.097V     1.139V     1.056V
236.5ps   1.067V     1.104V     1.036V
301.9ps   1.053V     1.08V      1.03V
407ps     1.049V     1.066V     1.031V
1.262ns   1.055V     1.066V     1.039V
